VERSION 5.8 ;
BUSBITCHARS "[]" ;
DIVIDERCHAR "/" ;
UNITS
    DATABASE MICRONS 1000 ;
END UNITS

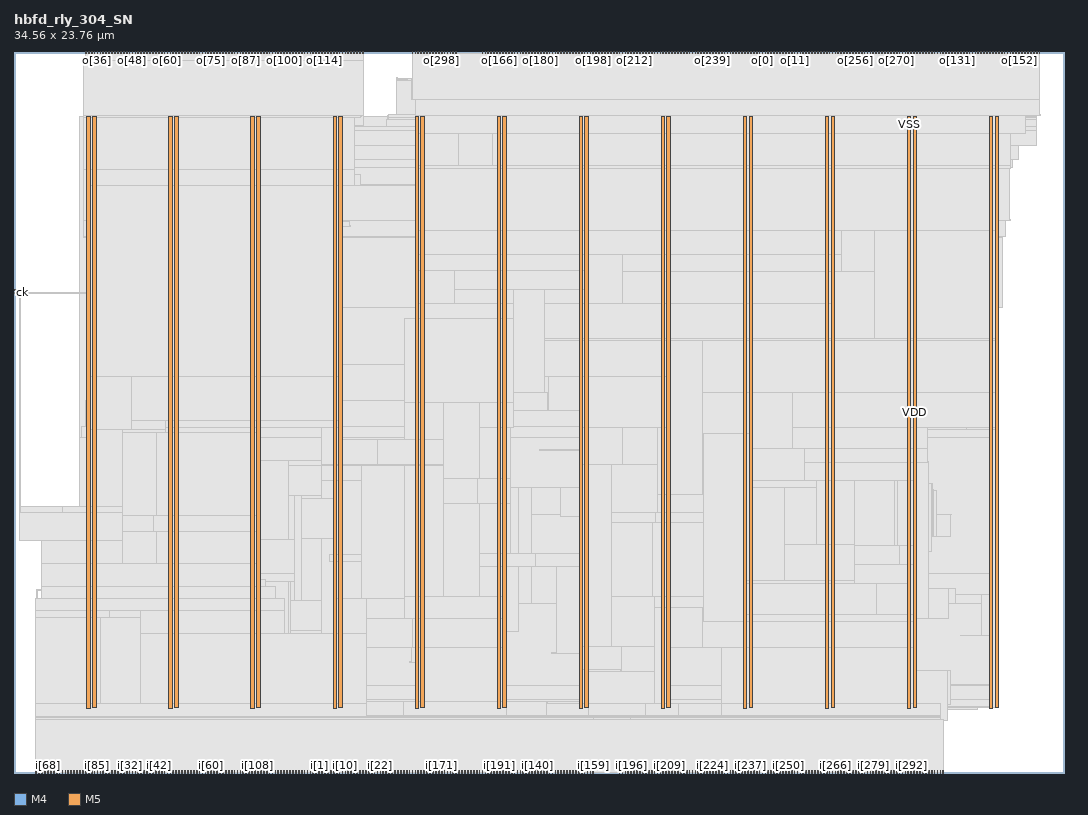
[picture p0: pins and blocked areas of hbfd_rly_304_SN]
MACRO hbfd_rly_304_SN
  FOREIGN hbfd_rly_304_SN 0 0 ;
  CLASS BLOCK ;
  SIZE 34.56 BY 23.76 ;
  PIN ck
    DIRECTION INPUT ;
    USE SIGNAL ;
    PORT
      LAYER M4 ;
        RECT  0 15.792 0.084 15.816 ;
    END
  END ck
  PIN i[0]
    DIRECTION INPUT ;
    USE SIGNAL ;
    PORT
      LAYER M5 ;
        RECT  9.936 0 9.96 0.084 ;
    END
  END i[0]
  PIN i[100]
    DIRECTION INPUT ;
    USE SIGNAL ;
    PORT
      LAYER M5 ;
        RECT  7.248 0 7.272 0.084 ;
    END
  END i[100]
  PIN i[101]
    DIRECTION INPUT ;
    USE SIGNAL ;
    PORT
      LAYER M5 ;
        RECT  7.344 0 7.368 0.084 ;
    END
  END i[101]
  PIN i[102]
    DIRECTION INPUT ;
    USE SIGNAL ;
    PORT
      LAYER M5 ;
        RECT  7.44 0 7.464 0.084 ;
    END
  END i[102]
  PIN i[103]
    DIRECTION INPUT ;
    USE SIGNAL ;
    PORT
      LAYER M5 ;
        RECT  7.536 0 7.56 0.084 ;
    END
  END i[103]
  PIN i[104]
    DIRECTION INPUT ;
    USE SIGNAL ;
    PORT
      LAYER M5 ;
        RECT  7.632 0 7.656 0.084 ;
    END
  END i[104]
  PIN i[105]
    DIRECTION INPUT ;
    USE SIGNAL ;
    PORT
      LAYER M5 ;
        RECT  7.728 0 7.752 0.084 ;
    END
  END i[105]
  PIN i[106]
    DIRECTION INPUT ;
    USE SIGNAL ;
    PORT
      LAYER M5 ;
        RECT  7.824 0 7.848 0.084 ;
    END
  END i[106]
  PIN i[107]
    DIRECTION INPUT ;
    USE SIGNAL ;
    PORT
      LAYER M5 ;
        RECT  7.92 0 7.944 0.084 ;
    END
  END i[107]
  PIN i[108]
    DIRECTION INPUT ;
    USE SIGNAL ;
    PORT
      LAYER M5 ;
        RECT  8.016 0 8.04 0.084 ;
    END
  END i[108]
  PIN i[109]
    DIRECTION INPUT ;
    USE SIGNAL ;
    PORT
      LAYER M5 ;
        RECT  8.112 0 8.136 0.084 ;
    END
  END i[109]
  PIN i[10]
    DIRECTION INPUT ;
    USE SIGNAL ;
    PORT
      LAYER M5 ;
        RECT  10.896 0 10.92 0.084 ;
    END
  END i[10]
  PIN i[110]
    DIRECTION INPUT ;
    USE SIGNAL ;
    PORT
      LAYER M5 ;
        RECT  8.208 0 8.232 0.084 ;
    END
  END i[110]
  PIN i[111]
    DIRECTION INPUT ;
    USE SIGNAL ;
    PORT
      LAYER M5 ;
        RECT  8.304 0 8.328 0.084 ;
    END
  END i[111]
  PIN i[112]
    DIRECTION INPUT ;
    USE SIGNAL ;
    PORT
      LAYER M5 ;
        RECT  8.4 0 8.424 0.084 ;
    END
  END i[112]
  PIN i[113]
    DIRECTION INPUT ;
    USE SIGNAL ;
    PORT
      LAYER M5 ;
        RECT  8.496 0 8.52 0.084 ;
    END
  END i[113]
  PIN i[114]
    DIRECTION INPUT ;
    USE SIGNAL ;
    PORT
      LAYER M5 ;
        RECT  8.592 0 8.616 0.084 ;
    END
  END i[114]
  PIN i[115]
    DIRECTION INPUT ;
    USE SIGNAL ;
    PORT
      LAYER M5 ;
        RECT  8.688 0 8.712 0.084 ;
    END
  END i[115]
  PIN i[116]
    DIRECTION INPUT ;
    USE SIGNAL ;
    PORT
      LAYER M5 ;
        RECT  8.784 0 8.808 0.084 ;
    END
  END i[116]
  PIN i[117]
    DIRECTION INPUT ;
    USE SIGNAL ;
    PORT
      LAYER M5 ;
        RECT  8.88 0 8.904 0.084 ;
    END
  END i[117]
  PIN i[118]
    DIRECTION INPUT ;
    USE SIGNAL ;
    PORT
      LAYER M5 ;
        RECT  8.976 0 9 0.084 ;
    END
  END i[118]
  PIN i[119]
    DIRECTION INPUT ;
    USE SIGNAL ;
    PORT
      LAYER M5 ;
        RECT  9.072 0 9.096 0.084 ;
    END
  END i[119]
  PIN i[11]
    DIRECTION INPUT ;
    USE SIGNAL ;
    PORT
      LAYER M5 ;
        RECT  10.992 0 11.016 0.084 ;
    END
  END i[11]
  PIN i[120]
    DIRECTION INPUT ;
    USE SIGNAL ;
    PORT
      LAYER M5 ;
        RECT  9.168 0 9.192 0.084 ;
    END
  END i[120]
  PIN i[121]
    DIRECTION INPUT ;
    USE SIGNAL ;
    PORT
      LAYER M5 ;
        RECT  9.264 0 9.288 0.084 ;
    END
  END i[121]
  PIN i[122]
    DIRECTION INPUT ;
    USE SIGNAL ;
    PORT
      LAYER M5 ;
        RECT  9.36 0 9.384 0.084 ;
    END
  END i[122]
  PIN i[123]
    DIRECTION INPUT ;
    USE SIGNAL ;
    PORT
      LAYER M5 ;
        RECT  9.456 0 9.48 0.084 ;
    END
  END i[123]
  PIN i[124]
    DIRECTION INPUT ;
    USE SIGNAL ;
    PORT
      LAYER M5 ;
        RECT  9.552 0 9.576 0.084 ;
    END
  END i[124]
  PIN i[125]
    DIRECTION INPUT ;
    USE SIGNAL ;
    PORT
      LAYER M5 ;
        RECT  9.648 0 9.672 0.084 ;
    END
  END i[125]
  PIN i[126]
    DIRECTION INPUT ;
    USE SIGNAL ;
    PORT
      LAYER M5 ;
        RECT  9.744 0 9.768 0.084 ;
    END
  END i[126]
  PIN i[127]
    DIRECTION INPUT ;
    USE SIGNAL ;
    PORT
      LAYER M5 ;
        RECT  9.84 0 9.864 0.084 ;
    END
  END i[127]
  PIN i[128]
    DIRECTION INPUT ;
    USE SIGNAL ;
    PORT
      LAYER M5 ;
        RECT  16.08 0 16.104 0.084 ;
    END
  END i[128]
  PIN i[129]
    DIRECTION INPUT ;
    USE SIGNAL ;
    PORT
      LAYER M5 ;
        RECT  16.176 0 16.2 0.084 ;
    END
  END i[129]
  PIN i[12]
    DIRECTION INPUT ;
    USE SIGNAL ;
    PORT
      LAYER M5 ;
        RECT  11.088 0 11.112 0.084 ;
    END
  END i[12]
  PIN i[130]
    DIRECTION INPUT ;
    USE SIGNAL ;
    PORT
      LAYER M5 ;
        RECT  16.272 0 16.296 0.084 ;
    END
  END i[130]
  PIN i[131]
    DIRECTION INPUT ;
    USE SIGNAL ;
    PORT
      LAYER M5 ;
        RECT  16.368 0 16.392 0.084 ;
    END
  END i[131]
  PIN i[132]
    DIRECTION INPUT ;
    USE SIGNAL ;
    PORT
      LAYER M5 ;
        RECT  16.464 0 16.488 0.084 ;
    END
  END i[132]
  PIN i[133]
    DIRECTION INPUT ;
    USE SIGNAL ;
    PORT
      LAYER M5 ;
        RECT  16.56 0 16.584 0.084 ;
    END
  END i[133]
  PIN i[134]
    DIRECTION INPUT ;
    USE SIGNAL ;
    PORT
      LAYER M5 ;
        RECT  16.656 0 16.68 0.084 ;
    END
  END i[134]
  PIN i[135]
    DIRECTION INPUT ;
    USE SIGNAL ;
    PORT
      LAYER M5 ;
        RECT  16.752 0 16.776 0.084 ;
    END
  END i[135]
  PIN i[136]
    DIRECTION INPUT ;
    USE SIGNAL ;
    PORT
      LAYER M5 ;
        RECT  16.848 0 16.872 0.084 ;
    END
  END i[136]
  PIN i[137]
    DIRECTION INPUT ;
    USE SIGNAL ;
    PORT
      LAYER M5 ;
        RECT  16.944 0 16.968 0.084 ;
    END
  END i[137]
  PIN i[138]
    DIRECTION INPUT ;
    USE SIGNAL ;
    PORT
      LAYER M5 ;
        RECT  17.04 0 17.064 0.084 ;
    END
  END i[138]
  PIN i[139]
    DIRECTION INPUT ;
    USE SIGNAL ;
    PORT
      LAYER M5 ;
        RECT  17.136 0 17.16 0.084 ;
    END
  END i[139]
  PIN i[13]
    DIRECTION INPUT ;
    USE SIGNAL ;
    PORT
      LAYER M5 ;
        RECT  11.184 0 11.208 0.084 ;
    END
  END i[13]
  PIN i[140]
    DIRECTION INPUT ;
    USE SIGNAL ;
    PORT
      LAYER M5 ;
        RECT  17.232 0 17.256 0.084 ;
    END
  END i[140]
  PIN i[141]
    DIRECTION INPUT ;
    USE SIGNAL ;
    PORT
      LAYER M5 ;
        RECT  17.328 0 17.352 0.084 ;
    END
  END i[141]
  PIN i[142]
    DIRECTION INPUT ;
    USE SIGNAL ;
    PORT
      LAYER M5 ;
        RECT  17.424 0 17.448 0.084 ;
    END
  END i[142]
  PIN i[143]
    DIRECTION INPUT ;
    USE SIGNAL ;
    PORT
      LAYER M5 ;
        RECT  17.52 0 17.544 0.084 ;
    END
  END i[143]
  PIN i[144]
    DIRECTION INPUT ;
    USE SIGNAL ;
    PORT
      LAYER M5 ;
        RECT  17.616 0 17.64 0.084 ;
    END
  END i[144]
  PIN i[145]
    DIRECTION INPUT ;
    USE SIGNAL ;
    PORT
      LAYER M5 ;
        RECT  17.712 0 17.736 0.084 ;
    END
  END i[145]
  PIN i[146]
    DIRECTION INPUT ;
    USE SIGNAL ;
    PORT
      LAYER M5 ;
        RECT  17.808 0 17.832 0.084 ;
    END
  END i[146]
  PIN i[147]
    DIRECTION INPUT ;
    USE SIGNAL ;
    PORT
      LAYER M5 ;
        RECT  17.904 0 17.928 0.084 ;
    END
  END i[147]
  PIN i[148]
    DIRECTION INPUT ;
    USE SIGNAL ;
    PORT
      LAYER M5 ;
        RECT  18 0 18.024 0.084 ;
    END
  END i[148]
  PIN i[149]
    DIRECTION INPUT ;
    USE SIGNAL ;
    PORT
      LAYER M5 ;
        RECT  18.096 0 18.12 0.084 ;
    END
  END i[149]
  PIN i[14]
    DIRECTION INPUT ;
    USE SIGNAL ;
    PORT
      LAYER M5 ;
        RECT  11.28 0 11.304 0.084 ;
    END
  END i[14]
  PIN i[150]
    DIRECTION INPUT ;
    USE SIGNAL ;
    PORT
      LAYER M5 ;
        RECT  18.192 0 18.216 0.084 ;
    END
  END i[150]
  PIN i[151]
    DIRECTION INPUT ;
    USE SIGNAL ;
    PORT
      LAYER M5 ;
        RECT  18.288 0 18.312 0.084 ;
    END
  END i[151]
  PIN i[152]
    DIRECTION INPUT ;
    USE SIGNAL ;
    PORT
      LAYER M5 ;
        RECT  18.384 0 18.408 0.084 ;
    END
  END i[152]
  PIN i[153]
    DIRECTION INPUT ;
    USE SIGNAL ;
    PORT
      LAYER M5 ;
        RECT  18.48 0 18.504 0.084 ;
    END
  END i[153]
  PIN i[154]
    DIRECTION INPUT ;
    USE SIGNAL ;
    PORT
      LAYER M5 ;
        RECT  18.576 0 18.6 0.084 ;
    END
  END i[154]
  PIN i[155]
    DIRECTION INPUT ;
    USE SIGNAL ;
    PORT
      LAYER M5 ;
        RECT  18.672 0 18.696 0.084 ;
    END
  END i[155]
  PIN i[156]
    DIRECTION INPUT ;
    USE SIGNAL ;
    PORT
      LAYER M5 ;
        RECT  18.768 0 18.792 0.084 ;
    END
  END i[156]
  PIN i[157]
    DIRECTION INPUT ;
    USE SIGNAL ;
    PORT
      LAYER M5 ;
        RECT  18.864 0 18.888 0.084 ;
    END
  END i[157]
  PIN i[158]
    DIRECTION INPUT ;
    USE SIGNAL ;
    PORT
      LAYER M5 ;
        RECT  18.96 0 18.984 0.084 ;
    END
  END i[158]
  PIN i[159]
    DIRECTION INPUT ;
    USE SIGNAL ;
    PORT
      LAYER M5 ;
        RECT  19.056 0 19.08 0.084 ;
    END
  END i[159]
  PIN i[15]
    DIRECTION INPUT ;
    USE SIGNAL ;
    PORT
      LAYER M5 ;
        RECT  11.376 0 11.4 0.084 ;
    END
  END i[15]
  PIN i[160]
    DIRECTION INPUT ;
    USE SIGNAL ;
    PORT
      LAYER M5 ;
        RECT  13.008 0 13.032 0.084 ;
    END
  END i[160]
  PIN i[161]
    DIRECTION INPUT ;
    USE SIGNAL ;
    PORT
      LAYER M5 ;
        RECT  13.104 0 13.128 0.084 ;
    END
  END i[161]
  PIN i[162]
    DIRECTION INPUT ;
    USE SIGNAL ;
    PORT
      LAYER M5 ;
        RECT  13.2 0 13.224 0.084 ;
    END
  END i[162]
  PIN i[163]
    DIRECTION INPUT ;
    USE SIGNAL ;
    PORT
      LAYER M5 ;
        RECT  13.296 0 13.32 0.084 ;
    END
  END i[163]
  PIN i[164]
    DIRECTION INPUT ;
    USE SIGNAL ;
    PORT
      LAYER M5 ;
        RECT  13.392 0 13.416 0.084 ;
    END
  END i[164]
  PIN i[165]
    DIRECTION INPUT ;
    USE SIGNAL ;
    PORT
      LAYER M5 ;
        RECT  13.488 0 13.512 0.084 ;
    END
  END i[165]
  PIN i[166]
    DIRECTION INPUT ;
    USE SIGNAL ;
    PORT
      LAYER M5 ;
        RECT  13.584 0 13.608 0.084 ;
    END
  END i[166]
  PIN i[167]
    DIRECTION INPUT ;
    USE SIGNAL ;
    PORT
      LAYER M5 ;
        RECT  13.68 0 13.704 0.084 ;
    END
  END i[167]
  PIN i[168]
    DIRECTION INPUT ;
    USE SIGNAL ;
    PORT
      LAYER M5 ;
        RECT  13.776 0 13.8 0.084 ;
    END
  END i[168]
  PIN i[169]
    DIRECTION INPUT ;
    USE SIGNAL ;
    PORT
      LAYER M5 ;
        RECT  13.872 0 13.896 0.084 ;
    END
  END i[169]
  PIN i[16]
    DIRECTION INPUT ;
    USE SIGNAL ;
    PORT
      LAYER M5 ;
        RECT  11.472 0 11.496 0.084 ;
    END
  END i[16]
  PIN i[170]
    DIRECTION INPUT ;
    USE SIGNAL ;
    PORT
      LAYER M5 ;
        RECT  13.968 0 13.992 0.084 ;
    END
  END i[170]
  PIN i[171]
    DIRECTION INPUT ;
    USE SIGNAL ;
    PORT
      LAYER M5 ;
        RECT  14.064 0 14.088 0.084 ;
    END
  END i[171]
  PIN i[172]
    DIRECTION INPUT ;
    USE SIGNAL ;
    PORT
      LAYER M5 ;
        RECT  14.16 0 14.184 0.084 ;
    END
  END i[172]
  PIN i[173]
    DIRECTION INPUT ;
    USE SIGNAL ;
    PORT
      LAYER M5 ;
        RECT  14.256 0 14.28 0.084 ;
    END
  END i[173]
  PIN i[174]
    DIRECTION INPUT ;
    USE SIGNAL ;
    PORT
      LAYER M5 ;
        RECT  14.352 0 14.376 0.084 ;
    END
  END i[174]
  PIN i[175]
    DIRECTION INPUT ;
    USE SIGNAL ;
    PORT
      LAYER M5 ;
        RECT  14.448 0 14.472 0.084 ;
    END
  END i[175]
  PIN i[176]
    DIRECTION INPUT ;
    USE SIGNAL ;
    PORT
      LAYER M5 ;
        RECT  14.544 0 14.568 0.084 ;
    END
  END i[176]
  PIN i[177]
    DIRECTION INPUT ;
    USE SIGNAL ;
    PORT
      LAYER M5 ;
        RECT  14.64 0 14.664 0.084 ;
    END
  END i[177]
  PIN i[178]
    DIRECTION INPUT ;
    USE SIGNAL ;
    PORT
      LAYER M5 ;
        RECT  14.736 0 14.76 0.084 ;
    END
  END i[178]
  PIN i[179]
    DIRECTION INPUT ;
    USE SIGNAL ;
    PORT
      LAYER M5 ;
        RECT  14.832 0 14.856 0.084 ;
    END
  END i[179]
  PIN i[17]
    DIRECTION INPUT ;
    USE SIGNAL ;
    PORT
      LAYER M5 ;
        RECT  11.568 0 11.592 0.084 ;
    END
  END i[17]
  PIN i[180]
    DIRECTION INPUT ;
    USE SIGNAL ;
    PORT
      LAYER M5 ;
        RECT  14.928 0 14.952 0.084 ;
    END
  END i[180]
  PIN i[181]
    DIRECTION INPUT ;
    USE SIGNAL ;
    PORT
      LAYER M5 ;
        RECT  15.024 0 15.048 0.084 ;
    END
  END i[181]
  PIN i[182]
    DIRECTION INPUT ;
    USE SIGNAL ;
    PORT
      LAYER M5 ;
        RECT  15.12 0 15.144 0.084 ;
    END
  END i[182]
  PIN i[183]
    DIRECTION INPUT ;
    USE SIGNAL ;
    PORT
      LAYER M5 ;
        RECT  15.216 0 15.24 0.084 ;
    END
  END i[183]
  PIN i[184]
    DIRECTION INPUT ;
    USE SIGNAL ;
    PORT
      LAYER M5 ;
        RECT  15.312 0 15.336 0.084 ;
    END
  END i[184]
  PIN i[185]
    DIRECTION INPUT ;
    USE SIGNAL ;
    PORT
      LAYER M5 ;
        RECT  15.408 0 15.432 0.084 ;
    END
  END i[185]
  PIN i[186]
    DIRECTION INPUT ;
    USE SIGNAL ;
    PORT
      LAYER M5 ;
        RECT  15.504 0 15.528 0.084 ;
    END
  END i[186]
  PIN i[187]
    DIRECTION INPUT ;
    USE SIGNAL ;
    PORT
      LAYER M5 ;
        RECT  15.6 0 15.624 0.084 ;
    END
  END i[187]
  PIN i[188]
    DIRECTION INPUT ;
    USE SIGNAL ;
    PORT
      LAYER M5 ;
        RECT  15.696 0 15.72 0.084 ;
    END
  END i[188]
  PIN i[189]
    DIRECTION INPUT ;
    USE SIGNAL ;
    PORT
      LAYER M5 ;
        RECT  15.792 0 15.816 0.084 ;
    END
  END i[189]
  PIN i[18]
    DIRECTION INPUT ;
    USE SIGNAL ;
    PORT
      LAYER M5 ;
        RECT  11.664 0 11.688 0.084 ;
    END
  END i[18]
  PIN i[190]
    DIRECTION INPUT ;
    USE SIGNAL ;
    PORT
      LAYER M5 ;
        RECT  15.888 0 15.912 0.084 ;
    END
  END i[190]
  PIN i[191]
    DIRECTION INPUT ;
    USE SIGNAL ;
    PORT
      LAYER M5 ;
        RECT  15.984 0 16.008 0.084 ;
    END
  END i[191]
  PIN i[192]
    DIRECTION INPUT ;
    USE SIGNAL ;
    PORT
      LAYER M5 ;
        RECT  19.92 0 19.944 0.084 ;
    END
  END i[192]
  PIN i[193]
    DIRECTION INPUT ;
    USE SIGNAL ;
    PORT
      LAYER M5 ;
        RECT  20.016 0 20.04 0.084 ;
    END
  END i[193]
  PIN i[194]
    DIRECTION INPUT ;
    USE SIGNAL ;
    PORT
      LAYER M5 ;
        RECT  20.112 0 20.136 0.084 ;
    END
  END i[194]
  PIN i[195]
    DIRECTION INPUT ;
    USE SIGNAL ;
    PORT
      LAYER M5 ;
        RECT  20.208 0 20.232 0.084 ;
    END
  END i[195]
  PIN i[196]
    DIRECTION INPUT ;
    USE SIGNAL ;
    PORT
      LAYER M5 ;
        RECT  20.304 0 20.328 0.084 ;
    END
  END i[196]
  PIN i[197]
    DIRECTION INPUT ;
    USE SIGNAL ;
    PORT
      LAYER M5 ;
        RECT  20.4 0 20.424 0.084 ;
    END
  END i[197]
  PIN i[198]
    DIRECTION INPUT ;
    USE SIGNAL ;
    PORT
      LAYER M5 ;
        RECT  20.496 0 20.52 0.084 ;
    END
  END i[198]
  PIN i[199]
    DIRECTION INPUT ;
    USE SIGNAL ;
    PORT
      LAYER M5 ;
        RECT  20.592 0 20.616 0.084 ;
    END
  END i[199]
  PIN i[19]
    DIRECTION INPUT ;
    USE SIGNAL ;
    PORT
      LAYER M5 ;
        RECT  11.76 0 11.784 0.084 ;
    END
  END i[19]
  PIN i[1]
    DIRECTION INPUT ;
    USE SIGNAL ;
    PORT
      LAYER M5 ;
        RECT  10.032 0 10.056 0.084 ;
    END
  END i[1]
  PIN i[200]
    DIRECTION INPUT ;
    USE SIGNAL ;
    PORT
      LAYER M5 ;
        RECT  20.688 0 20.712 0.084 ;
    END
  END i[200]
  PIN i[201]
    DIRECTION INPUT ;
    USE SIGNAL ;
    PORT
      LAYER M5 ;
        RECT  20.784 0 20.808 0.084 ;
    END
  END i[201]
  PIN i[202]
    DIRECTION INPUT ;
    USE SIGNAL ;
    PORT
      LAYER M5 ;
        RECT  20.88 0 20.904 0.084 ;
    END
  END i[202]
  PIN i[203]
    DIRECTION INPUT ;
    USE SIGNAL ;
    PORT
      LAYER M5 ;
        RECT  20.976 0 21 0.084 ;
    END
  END i[203]
  PIN i[204]
    DIRECTION INPUT ;
    USE SIGNAL ;
    PORT
      LAYER M5 ;
        RECT  21.072 0 21.096 0.084 ;
    END
  END i[204]
  PIN i[205]
    DIRECTION INPUT ;
    USE SIGNAL ;
    PORT
      LAYER M5 ;
        RECT  21.168 0 21.192 0.084 ;
    END
  END i[205]
  PIN i[206]
    DIRECTION INPUT ;
    USE SIGNAL ;
    PORT
      LAYER M5 ;
        RECT  21.264 0 21.288 0.084 ;
    END
  END i[206]
  PIN i[207]
    DIRECTION INPUT ;
    USE SIGNAL ;
    PORT
      LAYER M5 ;
        RECT  21.36 0 21.384 0.084 ;
    END
  END i[207]
  PIN i[208]
    DIRECTION INPUT ;
    USE SIGNAL ;
    PORT
      LAYER M5 ;
        RECT  21.456 0 21.48 0.084 ;
    END
  END i[208]
  PIN i[209]
    DIRECTION INPUT ;
    USE SIGNAL ;
    PORT
      LAYER M5 ;
        RECT  21.552 0 21.576 0.084 ;
    END
  END i[209]
  PIN i[20]
    DIRECTION INPUT ;
    USE SIGNAL ;
    PORT
      LAYER M5 ;
        RECT  11.856 0 11.88 0.084 ;
    END
  END i[20]
  PIN i[210]
    DIRECTION INPUT ;
    USE SIGNAL ;
    PORT
      LAYER M5 ;
        RECT  21.648 0 21.672 0.084 ;
    END
  END i[210]
  PIN i[211]
    DIRECTION INPUT ;
    USE SIGNAL ;
    PORT
      LAYER M5 ;
        RECT  21.744 0 21.768 0.084 ;
    END
  END i[211]
  PIN i[212]
    DIRECTION INPUT ;
    USE SIGNAL ;
    PORT
      LAYER M5 ;
        RECT  21.84 0 21.864 0.084 ;
    END
  END i[212]
  PIN i[213]
    DIRECTION INPUT ;
    USE SIGNAL ;
    PORT
      LAYER M5 ;
        RECT  21.936 0 21.96 0.084 ;
    END
  END i[213]
  PIN i[214]
    DIRECTION INPUT ;
    USE SIGNAL ;
    PORT
      LAYER M5 ;
        RECT  22.032 0 22.056 0.084 ;
    END
  END i[214]
  PIN i[215]
    DIRECTION INPUT ;
    USE SIGNAL ;
    PORT
      LAYER M5 ;
        RECT  22.128 0 22.152 0.084 ;
    END
  END i[215]
  PIN i[216]
    DIRECTION INPUT ;
    USE SIGNAL ;
    PORT
      LAYER M5 ;
        RECT  22.224 0 22.248 0.084 ;
    END
  END i[216]
  PIN i[217]
    DIRECTION INPUT ;
    USE SIGNAL ;
    PORT
      LAYER M5 ;
        RECT  22.32 0 22.344 0.084 ;
    END
  END i[217]
  PIN i[218]
    DIRECTION INPUT ;
    USE SIGNAL ;
    PORT
      LAYER M5 ;
        RECT  22.416 0 22.44 0.084 ;
    END
  END i[218]
  PIN i[219]
    DIRECTION INPUT ;
    USE SIGNAL ;
    PORT
      LAYER M5 ;
        RECT  22.512 0 22.536 0.084 ;
    END
  END i[219]
  PIN i[21]
    DIRECTION INPUT ;
    USE SIGNAL ;
    PORT
      LAYER M5 ;
        RECT  11.952 0 11.976 0.084 ;
    END
  END i[21]
  PIN i[220]
    DIRECTION INPUT ;
    USE SIGNAL ;
    PORT
      LAYER M5 ;
        RECT  22.608 0 22.632 0.084 ;
    END
  END i[220]
  PIN i[221]
    DIRECTION INPUT ;
    USE SIGNAL ;
    PORT
      LAYER M5 ;
        RECT  22.704 0 22.728 0.084 ;
    END
  END i[221]
  PIN i[222]
    DIRECTION INPUT ;
    USE SIGNAL ;
    PORT
      LAYER M5 ;
        RECT  22.8 0 22.824 0.084 ;
    END
  END i[222]
  PIN i[223]
    DIRECTION INPUT ;
    USE SIGNAL ;
    PORT
      LAYER M5 ;
        RECT  22.896 0 22.92 0.084 ;
    END
  END i[223]
  PIN i[224]
    DIRECTION INPUT ;
    USE SIGNAL ;
    PORT
      LAYER M5 ;
        RECT  22.992 0 23.016 0.084 ;
    END
  END i[224]
  PIN i[225]
    DIRECTION INPUT ;
    USE SIGNAL ;
    PORT
      LAYER M5 ;
        RECT  23.088 0 23.112 0.084 ;
    END
  END i[225]
  PIN i[226]
    DIRECTION INPUT ;
    USE SIGNAL ;
    PORT
      LAYER M5 ;
        RECT  23.184 0 23.208 0.084 ;
    END
  END i[226]
  PIN i[227]
    DIRECTION INPUT ;
    USE SIGNAL ;
    PORT
      LAYER M5 ;
        RECT  23.28 0 23.304 0.084 ;
    END
  END i[227]
  PIN i[228]
    DIRECTION INPUT ;
    USE SIGNAL ;
    PORT
      LAYER M5 ;
        RECT  23.376 0 23.4 0.084 ;
    END
  END i[228]
  PIN i[229]
    DIRECTION INPUT ;
    USE SIGNAL ;
    PORT
      LAYER M5 ;
        RECT  23.472 0 23.496 0.084 ;
    END
  END i[229]
  PIN i[22]
    DIRECTION INPUT ;
    USE SIGNAL ;
    PORT
      LAYER M5 ;
        RECT  12.048 0 12.072 0.084 ;
    END
  END i[22]
  PIN i[230]
    DIRECTION INPUT ;
    USE SIGNAL ;
    PORT
      LAYER M5 ;
        RECT  23.568 0 23.592 0.084 ;
    END
  END i[230]
  PIN i[231]
    DIRECTION INPUT ;
    USE SIGNAL ;
    PORT
      LAYER M5 ;
        RECT  23.664 0 23.688 0.084 ;
    END
  END i[231]
  PIN i[232]
    DIRECTION INPUT ;
    USE SIGNAL ;
    PORT
      LAYER M5 ;
        RECT  23.76 0 23.784 0.084 ;
    END
  END i[232]
  PIN i[233]
    DIRECTION INPUT ;
    USE SIGNAL ;
    PORT
      LAYER M5 ;
        RECT  23.856 0 23.88 0.084 ;
    END
  END i[233]
  PIN i[234]
    DIRECTION INPUT ;
    USE SIGNAL ;
    PORT
      LAYER M5 ;
        RECT  23.952 0 23.976 0.084 ;
    END
  END i[234]
  PIN i[235]
    DIRECTION INPUT ;
    USE SIGNAL ;
    PORT
      LAYER M5 ;
        RECT  24.048 0 24.072 0.084 ;
    END
  END i[235]
  PIN i[236]
    DIRECTION INPUT ;
    USE SIGNAL ;
    PORT
      LAYER M5 ;
        RECT  24.144 0 24.168 0.084 ;
    END
  END i[236]
  PIN i[237]
    DIRECTION INPUT ;
    USE SIGNAL ;
    PORT
      LAYER M5 ;
        RECT  24.24 0 24.264 0.084 ;
    END
  END i[237]
  PIN i[238]
    DIRECTION INPUT ;
    USE SIGNAL ;
    PORT
      LAYER M5 ;
        RECT  24.336 0 24.36 0.084 ;
    END
  END i[238]
  PIN i[239]
    DIRECTION INPUT ;
    USE SIGNAL ;
    PORT
      LAYER M5 ;
        RECT  24.432 0 24.456 0.084 ;
    END
  END i[239]
  PIN i[23]
    DIRECTION INPUT ;
    USE SIGNAL ;
    PORT
      LAYER M5 ;
        RECT  12.144 0 12.168 0.084 ;
    END
  END i[23]
  PIN i[240]
    DIRECTION INPUT ;
    USE SIGNAL ;
    PORT
      LAYER M5 ;
        RECT  24.528 0 24.552 0.084 ;
    END
  END i[240]
  PIN i[241]
    DIRECTION INPUT ;
    USE SIGNAL ;
    PORT
      LAYER M5 ;
        RECT  24.624 0 24.648 0.084 ;
    END
  END i[241]
  PIN i[242]
    DIRECTION INPUT ;
    USE SIGNAL ;
    PORT
      LAYER M5 ;
        RECT  24.72 0 24.744 0.084 ;
    END
  END i[242]
  PIN i[243]
    DIRECTION INPUT ;
    USE SIGNAL ;
    PORT
      LAYER M5 ;
        RECT  24.816 0 24.84 0.084 ;
    END
  END i[243]
  PIN i[244]
    DIRECTION INPUT ;
    USE SIGNAL ;
    PORT
      LAYER M5 ;
        RECT  24.912 0 24.936 0.084 ;
    END
  END i[244]
  PIN i[245]
    DIRECTION INPUT ;
    USE SIGNAL ;
    PORT
      LAYER M5 ;
        RECT  25.008 0 25.032 0.084 ;
    END
  END i[245]
  PIN i[246]
    DIRECTION INPUT ;
    USE SIGNAL ;
    PORT
      LAYER M5 ;
        RECT  25.104 0 25.128 0.084 ;
    END
  END i[246]
  PIN i[247]
    DIRECTION INPUT ;
    USE SIGNAL ;
    PORT
      LAYER M5 ;
        RECT  25.2 0 25.224 0.084 ;
    END
  END i[247]
  PIN i[248]
    DIRECTION INPUT ;
    USE SIGNAL ;
    PORT
      LAYER M5 ;
        RECT  25.296 0 25.32 0.084 ;
    END
  END i[248]
  PIN i[249]
    DIRECTION INPUT ;
    USE SIGNAL ;
    PORT
      LAYER M5 ;
        RECT  25.392 0 25.416 0.084 ;
    END
  END i[249]
  PIN i[24]
    DIRECTION INPUT ;
    USE SIGNAL ;
    PORT
      LAYER M5 ;
        RECT  12.24 0 12.264 0.084 ;
    END
  END i[24]
  PIN i[250]
    DIRECTION INPUT ;
    USE SIGNAL ;
    PORT
      LAYER M5 ;
        RECT  25.488 0 25.512 0.084 ;
    END
  END i[250]
  PIN i[251]
    DIRECTION INPUT ;
    USE SIGNAL ;
    PORT
      LAYER M5 ;
        RECT  25.584 0 25.608 0.084 ;
    END
  END i[251]
  PIN i[252]
    DIRECTION INPUT ;
    USE SIGNAL ;
    PORT
      LAYER M5 ;
        RECT  25.68 0 25.704 0.084 ;
    END
  END i[252]
  PIN i[253]
    DIRECTION INPUT ;
    USE SIGNAL ;
    PORT
      LAYER M5 ;
        RECT  25.776 0 25.8 0.084 ;
    END
  END i[253]
  PIN i[254]
    DIRECTION INPUT ;
    USE SIGNAL ;
    PORT
      LAYER M5 ;
        RECT  25.872 0 25.896 0.084 ;
    END
  END i[254]
  PIN i[255]
    DIRECTION INPUT ;
    USE SIGNAL ;
    PORT
      LAYER M5 ;
        RECT  25.968 0 25.992 0.084 ;
    END
  END i[255]
  PIN i[256]
    DIRECTION INPUT ;
    USE SIGNAL ;
    PORT
      LAYER M5 ;
        RECT  26.064 0 26.088 0.084 ;
    END
  END i[256]
  PIN i[257]
    DIRECTION INPUT ;
    USE SIGNAL ;
    PORT
      LAYER M5 ;
        RECT  26.16 0 26.184 0.084 ;
    END
  END i[257]
  PIN i[258]
    DIRECTION INPUT ;
    USE SIGNAL ;
    PORT
      LAYER M5 ;
        RECT  26.256 0 26.28 0.084 ;
    END
  END i[258]
  PIN i[259]
    DIRECTION INPUT ;
    USE SIGNAL ;
    PORT
      LAYER M5 ;
        RECT  26.352 0 26.376 0.084 ;
    END
  END i[259]
  PIN i[25]
    DIRECTION INPUT ;
    USE SIGNAL ;
    PORT
      LAYER M5 ;
        RECT  12.336 0 12.36 0.084 ;
    END
  END i[25]
  PIN i[260]
    DIRECTION INPUT ;
    USE SIGNAL ;
    PORT
      LAYER M5 ;
        RECT  26.448 0 26.472 0.084 ;
    END
  END i[260]
  PIN i[261]
    DIRECTION INPUT ;
    USE SIGNAL ;
    PORT
      LAYER M5 ;
        RECT  26.544 0 26.568 0.084 ;
    END
  END i[261]
  PIN i[262]
    DIRECTION INPUT ;
    USE SIGNAL ;
    PORT
      LAYER M5 ;
        RECT  26.64 0 26.664 0.084 ;
    END
  END i[262]
  PIN i[263]
    DIRECTION INPUT ;
    USE SIGNAL ;
    PORT
      LAYER M5 ;
        RECT  26.736 0 26.76 0.084 ;
    END
  END i[263]
  PIN i[264]
    DIRECTION INPUT ;
    USE SIGNAL ;
    PORT
      LAYER M5 ;
        RECT  26.832 0 26.856 0.084 ;
    END
  END i[264]
  PIN i[265]
    DIRECTION INPUT ;
    USE SIGNAL ;
    PORT
      LAYER M5 ;
        RECT  26.928 0 26.952 0.084 ;
    END
  END i[265]
  PIN i[266]
    DIRECTION INPUT ;
    USE SIGNAL ;
    PORT
      LAYER M5 ;
        RECT  27.024 0 27.048 0.084 ;
    END
  END i[266]
  PIN i[267]
    DIRECTION INPUT ;
    USE SIGNAL ;
    PORT
      LAYER M5 ;
        RECT  27.12 0 27.144 0.084 ;
    END
  END i[267]
  PIN i[268]
    DIRECTION INPUT ;
    USE SIGNAL ;
    PORT
      LAYER M5 ;
        RECT  27.216 0 27.24 0.084 ;
    END
  END i[268]
  PIN i[269]
    DIRECTION INPUT ;
    USE SIGNAL ;
    PORT
      LAYER M5 ;
        RECT  27.312 0 27.336 0.084 ;
    END
  END i[269]
  PIN i[26]
    DIRECTION INPUT ;
    USE SIGNAL ;
    PORT
      LAYER M5 ;
        RECT  12.432 0 12.456 0.084 ;
    END
  END i[26]
  PIN i[270]
    DIRECTION INPUT ;
    USE SIGNAL ;
    PORT
      LAYER M5 ;
        RECT  27.408 0 27.432 0.084 ;
    END
  END i[270]
  PIN i[271]
    DIRECTION INPUT ;
    USE SIGNAL ;
    PORT
      LAYER M5 ;
        RECT  27.504 0 27.528 0.084 ;
    END
  END i[271]
  PIN i[272]
    DIRECTION INPUT ;
    USE SIGNAL ;
    PORT
      LAYER M5 ;
        RECT  27.6 0 27.624 0.084 ;
    END
  END i[272]
  PIN i[273]
    DIRECTION INPUT ;
    USE SIGNAL ;
    PORT
      LAYER M5 ;
        RECT  27.696 0 27.72 0.084 ;
    END
  END i[273]
  PIN i[274]
    DIRECTION INPUT ;
    USE SIGNAL ;
    PORT
      LAYER M5 ;
        RECT  27.792 0 27.816 0.084 ;
    END
  END i[274]
  PIN i[275]
    DIRECTION INPUT ;
    USE SIGNAL ;
    PORT
      LAYER M5 ;
        RECT  27.888 0 27.912 0.084 ;
    END
  END i[275]
  PIN i[276]
    DIRECTION INPUT ;
    USE SIGNAL ;
    PORT
      LAYER M5 ;
        RECT  27.984 0 28.008 0.084 ;
    END
  END i[276]
  PIN i[277]
    DIRECTION INPUT ;
    USE SIGNAL ;
    PORT
      LAYER M5 ;
        RECT  28.08 0 28.104 0.084 ;
    END
  END i[277]
  PIN i[278]
    DIRECTION INPUT ;
    USE SIGNAL ;
    PORT
      LAYER M5 ;
        RECT  28.176 0 28.2 0.084 ;
    END
  END i[278]
  PIN i[279]
    DIRECTION INPUT ;
    USE SIGNAL ;
    PORT
      LAYER M5 ;
        RECT  28.272 0 28.296 0.084 ;
    END
  END i[279]
  PIN i[27]
    DIRECTION INPUT ;
    USE SIGNAL ;
    PORT
      LAYER M5 ;
        RECT  12.528 0 12.552 0.084 ;
    END
  END i[27]
  PIN i[280]
    DIRECTION INPUT ;
    USE SIGNAL ;
    PORT
      LAYER M5 ;
        RECT  28.368 0 28.392 0.084 ;
    END
  END i[280]
  PIN i[281]
    DIRECTION INPUT ;
    USE SIGNAL ;
    PORT
      LAYER M5 ;
        RECT  28.464 0 28.488 0.084 ;
    END
  END i[281]
  PIN i[282]
    DIRECTION INPUT ;
    USE SIGNAL ;
    PORT
      LAYER M5 ;
        RECT  28.56 0 28.584 0.084 ;
    END
  END i[282]
  PIN i[283]
    DIRECTION INPUT ;
    USE SIGNAL ;
    PORT
      LAYER M5 ;
        RECT  28.656 0 28.68 0.084 ;
    END
  END i[283]
  PIN i[284]
    DIRECTION INPUT ;
    USE SIGNAL ;
    PORT
      LAYER M5 ;
        RECT  28.752 0 28.776 0.084 ;
    END
  END i[284]
  PIN i[285]
    DIRECTION INPUT ;
    USE SIGNAL ;
    PORT
      LAYER M5 ;
        RECT  28.848 0 28.872 0.084 ;
    END
  END i[285]
  PIN i[286]
    DIRECTION INPUT ;
    USE SIGNAL ;
    PORT
      LAYER M5 ;
        RECT  28.944 0 28.968 0.084 ;
    END
  END i[286]
  PIN i[287]
    DIRECTION INPUT ;
    USE SIGNAL ;
    PORT
      LAYER M5 ;
        RECT  29.04 0 29.064 0.084 ;
    END
  END i[287]
  PIN i[288]
    DIRECTION INPUT ;
    USE SIGNAL ;
    PORT
      LAYER M5 ;
        RECT  29.136 0 29.16 0.084 ;
    END
  END i[288]
  PIN i[289]
    DIRECTION INPUT ;
    USE SIGNAL ;
    PORT
      LAYER M5 ;
        RECT  29.232 0 29.256 0.084 ;
    END
  END i[289]
  PIN i[28]
    DIRECTION INPUT ;
    USE SIGNAL ;
    PORT
      LAYER M5 ;
        RECT  12.624 0 12.648 0.084 ;
    END
  END i[28]
  PIN i[290]
    DIRECTION INPUT ;
    USE SIGNAL ;
    PORT
      LAYER M5 ;
        RECT  29.328 0 29.352 0.084 ;
    END
  END i[290]
  PIN i[291]
    DIRECTION INPUT ;
    USE SIGNAL ;
    PORT
      LAYER M5 ;
        RECT  29.424 0 29.448 0.084 ;
    END
  END i[291]
  PIN i[292]
    DIRECTION INPUT ;
    USE SIGNAL ;
    PORT
      LAYER M5 ;
        RECT  29.52 0 29.544 0.084 ;
    END
  END i[292]
  PIN i[293]
    DIRECTION INPUT ;
    USE SIGNAL ;
    PORT
      LAYER M5 ;
        RECT  29.616 0 29.64 0.084 ;
    END
  END i[293]
  PIN i[294]
    DIRECTION INPUT ;
    USE SIGNAL ;
    PORT
      LAYER M5 ;
        RECT  29.712 0 29.736 0.084 ;
    END
  END i[294]
  PIN i[295]
    DIRECTION INPUT ;
    USE SIGNAL ;
    PORT
      LAYER M5 ;
        RECT  29.808 0 29.832 0.084 ;
    END
  END i[295]
  PIN i[296]
    DIRECTION INPUT ;
    USE SIGNAL ;
    PORT
      LAYER M5 ;
        RECT  29.904 0 29.928 0.084 ;
    END
  END i[296]
  PIN i[297]
    DIRECTION INPUT ;
    USE SIGNAL ;
    PORT
      LAYER M5 ;
        RECT  30 0 30.024 0.084 ;
    END
  END i[297]
  PIN i[298]
    DIRECTION INPUT ;
    USE SIGNAL ;
    PORT
      LAYER M5 ;
        RECT  30.096 0 30.12 0.084 ;
    END
  END i[298]
  PIN i[299]
    DIRECTION INPUT ;
    USE SIGNAL ;
    PORT
      LAYER M5 ;
        RECT  30.192 0 30.216 0.084 ;
    END
  END i[299]
  PIN i[29]
    DIRECTION INPUT ;
    USE SIGNAL ;
    PORT
      LAYER M5 ;
        RECT  12.72 0 12.744 0.084 ;
    END
  END i[29]
  PIN i[2]
    DIRECTION INPUT ;
    USE SIGNAL ;
    PORT
      LAYER M5 ;
        RECT  10.128 0 10.152 0.084 ;
    END
  END i[2]
  PIN i[300]
    DIRECTION INPUT ;
    USE SIGNAL ;
    PORT
      LAYER M5 ;
        RECT  30.288 0 30.312 0.084 ;
    END
  END i[300]
  PIN i[301]
    DIRECTION INPUT ;
    USE SIGNAL ;
    PORT
      LAYER M5 ;
        RECT  30.384 0 30.408 0.084 ;
    END
  END i[301]
  PIN i[302]
    DIRECTION INPUT ;
    USE SIGNAL ;
    PORT
      LAYER M5 ;
        RECT  30.48 0 30.504 0.084 ;
    END
  END i[302]
  PIN i[303]
    DIRECTION INPUT ;
    USE SIGNAL ;
    PORT
      LAYER M5 ;
        RECT  30.576 0 30.6 0.084 ;
    END
  END i[303]
  PIN i[30]
    DIRECTION INPUT ;
    USE SIGNAL ;
    PORT
      LAYER M5 ;
        RECT  12.816 0 12.84 0.084 ;
    END
  END i[30]
  PIN i[31]
    DIRECTION INPUT ;
    USE SIGNAL ;
    PORT
      LAYER M5 ;
        RECT  12.912 0 12.936 0.084 ;
    END
  END i[31]
  PIN i[32]
    DIRECTION INPUT ;
    USE SIGNAL ;
    PORT
      LAYER M5 ;
        RECT  3.792 0 3.816 0.084 ;
    END
  END i[32]
  PIN i[33]
    DIRECTION INPUT ;
    USE SIGNAL ;
    PORT
      LAYER M5 ;
        RECT  3.888 0 3.912 0.084 ;
    END
  END i[33]
  PIN i[34]
    DIRECTION INPUT ;
    USE SIGNAL ;
    PORT
      LAYER M5 ;
        RECT  3.984 0 4.008 0.084 ;
    END
  END i[34]
  PIN i[35]
    DIRECTION INPUT ;
    USE SIGNAL ;
    PORT
      LAYER M5 ;
        RECT  4.08 0 4.104 0.084 ;
    END
  END i[35]
  PIN i[36]
    DIRECTION INPUT ;
    USE SIGNAL ;
    PORT
      LAYER M5 ;
        RECT  4.176 0 4.2 0.084 ;
    END
  END i[36]
  PIN i[37]
    DIRECTION INPUT ;
    USE SIGNAL ;
    PORT
      LAYER M5 ;
        RECT  4.272 0 4.296 0.084 ;
    END
  END i[37]
  PIN i[38]
    DIRECTION INPUT ;
    USE SIGNAL ;
    PORT
      LAYER M5 ;
        RECT  4.368 0 4.392 0.084 ;
    END
  END i[38]
  PIN i[39]
    DIRECTION INPUT ;
    USE SIGNAL ;
    PORT
      LAYER M5 ;
        RECT  4.464 0 4.488 0.084 ;
    END
  END i[39]
  PIN i[3]
    DIRECTION INPUT ;
    USE SIGNAL ;
    PORT
      LAYER M5 ;
        RECT  10.224 0 10.248 0.084 ;
    END
  END i[3]
  PIN i[40]
    DIRECTION INPUT ;
    USE SIGNAL ;
    PORT
      LAYER M5 ;
        RECT  4.56 0 4.584 0.084 ;
    END
  END i[40]
  PIN i[41]
    DIRECTION INPUT ;
    USE SIGNAL ;
    PORT
      LAYER M5 ;
        RECT  4.656 0 4.68 0.084 ;
    END
  END i[41]
  PIN i[42]
    DIRECTION INPUT ;
    USE SIGNAL ;
    PORT
      LAYER M5 ;
        RECT  4.752 0 4.776 0.084 ;
    END
  END i[42]
  PIN i[43]
    DIRECTION INPUT ;
    USE SIGNAL ;
    PORT
      LAYER M5 ;
        RECT  4.848 0 4.872 0.084 ;
    END
  END i[43]
  PIN i[44]
    DIRECTION INPUT ;
    USE SIGNAL ;
    PORT
      LAYER M5 ;
        RECT  4.944 0 4.968 0.084 ;
    END
  END i[44]
  PIN i[45]
    DIRECTION INPUT ;
    USE SIGNAL ;
    PORT
      LAYER M5 ;
        RECT  5.04 0 5.064 0.084 ;
    END
  END i[45]
  PIN i[46]
    DIRECTION INPUT ;
    USE SIGNAL ;
    PORT
      LAYER M5 ;
        RECT  5.136 0 5.16 0.084 ;
    END
  END i[46]
  PIN i[47]
    DIRECTION INPUT ;
    USE SIGNAL ;
    PORT
      LAYER M5 ;
        RECT  5.232 0 5.256 0.084 ;
    END
  END i[47]
  PIN i[48]
    DIRECTION INPUT ;
    USE SIGNAL ;
    PORT
      LAYER M5 ;
        RECT  5.328 0 5.352 0.084 ;
    END
  END i[48]
  PIN i[49]
    DIRECTION INPUT ;
    USE SIGNAL ;
    PORT
      LAYER M5 ;
        RECT  5.424 0 5.448 0.084 ;
    END
  END i[49]
  PIN i[4]
    DIRECTION INPUT ;
    USE SIGNAL ;
    PORT
      LAYER M5 ;
        RECT  10.32 0 10.344 0.084 ;
    END
  END i[4]
  PIN i[50]
    DIRECTION INPUT ;
    USE SIGNAL ;
    PORT
      LAYER M5 ;
        RECT  5.52 0 5.544 0.084 ;
    END
  END i[50]
  PIN i[51]
    DIRECTION INPUT ;
    USE SIGNAL ;
    PORT
      LAYER M5 ;
        RECT  5.616 0 5.64 0.084 ;
    END
  END i[51]
  PIN i[52]
    DIRECTION INPUT ;
    USE SIGNAL ;
    PORT
      LAYER M5 ;
        RECT  5.712 0 5.736 0.084 ;
    END
  END i[52]
  PIN i[53]
    DIRECTION INPUT ;
    USE SIGNAL ;
    PORT
      LAYER M5 ;
        RECT  5.808 0 5.832 0.084 ;
    END
  END i[53]
  PIN i[54]
    DIRECTION INPUT ;
    USE SIGNAL ;
    PORT
      LAYER M5 ;
        RECT  5.904 0 5.928 0.084 ;
    END
  END i[54]
  PIN i[55]
    DIRECTION INPUT ;
    USE SIGNAL ;
    PORT
      LAYER M5 ;
        RECT  6 0 6.024 0.084 ;
    END
  END i[55]
  PIN i[56]
    DIRECTION INPUT ;
    USE SIGNAL ;
    PORT
      LAYER M5 ;
        RECT  6.096 0 6.12 0.084 ;
    END
  END i[56]
  PIN i[57]
    DIRECTION INPUT ;
    USE SIGNAL ;
    PORT
      LAYER M5 ;
        RECT  6.192 0 6.216 0.084 ;
    END
  END i[57]
  PIN i[58]
    DIRECTION INPUT ;
    USE SIGNAL ;
    PORT
      LAYER M5 ;
        RECT  6.288 0 6.312 0.084 ;
    END
  END i[58]
  PIN i[59]
    DIRECTION INPUT ;
    USE SIGNAL ;
    PORT
      LAYER M5 ;
        RECT  6.384 0 6.408 0.084 ;
    END
  END i[59]
  PIN i[5]
    DIRECTION INPUT ;
    USE SIGNAL ;
    PORT
      LAYER M5 ;
        RECT  10.416 0 10.44 0.084 ;
    END
  END i[5]
  PIN i[60]
    DIRECTION INPUT ;
    USE SIGNAL ;
    PORT
      LAYER M5 ;
        RECT  6.48 0 6.504 0.084 ;
    END
  END i[60]
  PIN i[61]
    DIRECTION INPUT ;
    USE SIGNAL ;
    PORT
      LAYER M5 ;
        RECT  6.576 0 6.6 0.084 ;
    END
  END i[61]
  PIN i[62]
    DIRECTION INPUT ;
    USE SIGNAL ;
    PORT
      LAYER M5 ;
        RECT  6.672 0 6.696 0.084 ;
    END
  END i[62]
  PIN i[63]
    DIRECTION INPUT ;
    USE SIGNAL ;
    PORT
      LAYER M5 ;
        RECT  6.768 0 6.792 0.084 ;
    END
  END i[63]
  PIN i[64]
    DIRECTION INPUT ;
    USE SIGNAL ;
    PORT
      LAYER M5 ;
        RECT  0.72 0 0.744 0.084 ;
    END
  END i[64]
  PIN i[65]
    DIRECTION INPUT ;
    USE SIGNAL ;
    PORT
      LAYER M5 ;
        RECT  0.816 0 0.84 0.084 ;
    END
  END i[65]
  PIN i[66]
    DIRECTION INPUT ;
    USE SIGNAL ;
    PORT
      LAYER M5 ;
        RECT  0.912 0 0.936 0.084 ;
    END
  END i[66]
  PIN i[67]
    DIRECTION INPUT ;
    USE SIGNAL ;
    PORT
      LAYER M5 ;
        RECT  1.008 0 1.032 0.084 ;
    END
  END i[67]
  PIN i[68]
    DIRECTION INPUT ;
    USE SIGNAL ;
    PORT
      LAYER M5 ;
        RECT  1.104 0 1.128 0.084 ;
    END
  END i[68]
  PIN i[69]
    DIRECTION INPUT ;
    USE SIGNAL ;
    PORT
      LAYER M5 ;
        RECT  1.2 0 1.224 0.084 ;
    END
  END i[69]
  PIN i[6]
    DIRECTION INPUT ;
    USE SIGNAL ;
    PORT
      LAYER M5 ;
        RECT  10.512 0 10.536 0.084 ;
    END
  END i[6]
  PIN i[70]
    DIRECTION INPUT ;
    USE SIGNAL ;
    PORT
      LAYER M5 ;
        RECT  1.296 0 1.32 0.084 ;
    END
  END i[70]
  PIN i[71]
    DIRECTION INPUT ;
    USE SIGNAL ;
    PORT
      LAYER M5 ;
        RECT  1.392 0 1.416 0.084 ;
    END
  END i[71]
  PIN i[72]
    DIRECTION INPUT ;
    USE SIGNAL ;
    PORT
      LAYER M5 ;
        RECT  1.488 0 1.512 0.084 ;
    END
  END i[72]
  PIN i[73]
    DIRECTION INPUT ;
    USE SIGNAL ;
    PORT
      LAYER M5 ;
        RECT  1.584 0 1.608 0.084 ;
    END
  END i[73]
  PIN i[74]
    DIRECTION INPUT ;
    USE SIGNAL ;
    PORT
      LAYER M5 ;
        RECT  1.68 0 1.704 0.084 ;
    END
  END i[74]
  PIN i[75]
    DIRECTION INPUT ;
    USE SIGNAL ;
    PORT
      LAYER M5 ;
        RECT  1.776 0 1.8 0.084 ;
    END
  END i[75]
  PIN i[76]
    DIRECTION INPUT ;
    USE SIGNAL ;
    PORT
      LAYER M5 ;
        RECT  1.872 0 1.896 0.084 ;
    END
  END i[76]
  PIN i[77]
    DIRECTION INPUT ;
    USE SIGNAL ;
    PORT
      LAYER M5 ;
        RECT  1.968 0 1.992 0.084 ;
    END
  END i[77]
  PIN i[78]
    DIRECTION INPUT ;
    USE SIGNAL ;
    PORT
      LAYER M5 ;
        RECT  2.064 0 2.088 0.084 ;
    END
  END i[78]
  PIN i[79]
    DIRECTION INPUT ;
    USE SIGNAL ;
    PORT
      LAYER M5 ;
        RECT  2.16 0 2.184 0.084 ;
    END
  END i[79]
  PIN i[7]
    DIRECTION INPUT ;
    USE SIGNAL ;
    PORT
      LAYER M5 ;
        RECT  10.608 0 10.632 0.084 ;
    END
  END i[7]
  PIN i[80]
    DIRECTION INPUT ;
    USE SIGNAL ;
    PORT
      LAYER M5 ;
        RECT  2.256 0 2.28 0.084 ;
    END
  END i[80]
  PIN i[81]
    DIRECTION INPUT ;
    USE SIGNAL ;
    PORT
      LAYER M5 ;
        RECT  2.352 0 2.376 0.084 ;
    END
  END i[81]
  PIN i[82]
    DIRECTION INPUT ;
    USE SIGNAL ;
    PORT
      LAYER M5 ;
        RECT  2.448 0 2.472 0.084 ;
    END
  END i[82]
  PIN i[83]
    DIRECTION INPUT ;
    USE SIGNAL ;
    PORT
      LAYER M5 ;
        RECT  2.544 0 2.568 0.084 ;
    END
  END i[83]
  PIN i[84]
    DIRECTION INPUT ;
    USE SIGNAL ;
    PORT
      LAYER M5 ;
        RECT  2.64 0 2.664 0.084 ;
    END
  END i[84]
  PIN i[85]
    DIRECTION INPUT ;
    USE SIGNAL ;
    PORT
      LAYER M5 ;
        RECT  2.736 0 2.76 0.084 ;
    END
  END i[85]
  PIN i[86]
    DIRECTION INPUT ;
    USE SIGNAL ;
    PORT
      LAYER M5 ;
        RECT  2.832 0 2.856 0.084 ;
    END
  END i[86]
  PIN i[87]
    DIRECTION INPUT ;
    USE SIGNAL ;
    PORT
      LAYER M5 ;
        RECT  2.928 0 2.952 0.084 ;
    END
  END i[87]
  PIN i[88]
    DIRECTION INPUT ;
    USE SIGNAL ;
    PORT
      LAYER M5 ;
        RECT  3.024 0 3.048 0.084 ;
    END
  END i[88]
  PIN i[89]
    DIRECTION INPUT ;
    USE SIGNAL ;
    PORT
      LAYER M5 ;
        RECT  3.12 0 3.144 0.084 ;
    END
  END i[89]
  PIN i[8]
    DIRECTION INPUT ;
    USE SIGNAL ;
    PORT
      LAYER M5 ;
        RECT  10.704 0 10.728 0.084 ;
    END
  END i[8]
  PIN i[90]
    DIRECTION INPUT ;
    USE SIGNAL ;
    PORT
      LAYER M5 ;
        RECT  3.216 0 3.24 0.084 ;
    END
  END i[90]
  PIN i[91]
    DIRECTION INPUT ;
    USE SIGNAL ;
    PORT
      LAYER M5 ;
        RECT  3.312 0 3.336 0.084 ;
    END
  END i[91]
  PIN i[92]
    DIRECTION INPUT ;
    USE SIGNAL ;
    PORT
      LAYER M5 ;
        RECT  3.408 0 3.432 0.084 ;
    END
  END i[92]
  PIN i[93]
    DIRECTION INPUT ;
    USE SIGNAL ;
    PORT
      LAYER M5 ;
        RECT  3.504 0 3.528 0.084 ;
    END
  END i[93]
  PIN i[94]
    DIRECTION INPUT ;
    USE SIGNAL ;
    PORT
      LAYER M5 ;
        RECT  3.6 0 3.624 0.084 ;
    END
  END i[94]
  PIN i[95]
    DIRECTION INPUT ;
    USE SIGNAL ;
    PORT
      LAYER M5 ;
        RECT  3.696 0 3.72 0.084 ;
    END
  END i[95]
  PIN i[96]
    DIRECTION INPUT ;
    USE SIGNAL ;
    PORT
      LAYER M5 ;
        RECT  6.864 0 6.888 0.084 ;
    END
  END i[96]
  PIN i[97]
    DIRECTION INPUT ;
    USE SIGNAL ;
    PORT
      LAYER M5 ;
        RECT  6.96 0 6.984 0.084 ;
    END
  END i[97]
  PIN i[98]
    DIRECTION INPUT ;
    USE SIGNAL ;
    PORT
      LAYER M5 ;
        RECT  7.056 0 7.08 0.084 ;
    END
  END i[98]
  PIN i[99]
    DIRECTION INPUT ;
    USE SIGNAL ;
    PORT
      LAYER M5 ;
        RECT  7.152 0 7.176 0.084 ;
    END
  END i[99]
  PIN i[9]
    DIRECTION INPUT ;
    USE SIGNAL ;
    PORT
      LAYER M5 ;
        RECT  10.8 0 10.824 0.084 ;
    END
  END i[9]
  PIN o[0]
    DIRECTION OUTPUT ;
    USE SIGNAL ;
    PORT
      LAYER M5 ;
        RECT  24.624 23.676 24.648 23.76 ;
    END
  END o[0]
  PIN o[100]
    DIRECTION OUTPUT ;
    USE SIGNAL ;
    PORT
      LAYER M5 ;
        RECT  8.88 23.676 8.904 23.76 ;
    END
  END o[100]
  PIN o[101]
    DIRECTION OUTPUT ;
    USE SIGNAL ;
    PORT
      LAYER M5 ;
        RECT  8.976 23.676 9 23.76 ;
    END
  END o[101]
  PIN o[102]
    DIRECTION OUTPUT ;
    USE SIGNAL ;
    PORT
      LAYER M5 ;
        RECT  9.072 23.676 9.096 23.76 ;
    END
  END o[102]
  PIN o[103]
    DIRECTION OUTPUT ;
    USE SIGNAL ;
    PORT
      LAYER M5 ;
        RECT  9.168 23.676 9.192 23.76 ;
    END
  END o[103]
  PIN o[104]
    DIRECTION OUTPUT ;
    USE SIGNAL ;
    PORT
      LAYER M5 ;
        RECT  9.264 23.676 9.288 23.76 ;
    END
  END o[104]
  PIN o[105]
    DIRECTION OUTPUT ;
    USE SIGNAL ;
    PORT
      LAYER M5 ;
        RECT  9.36 23.676 9.384 23.76 ;
    END
  END o[105]
  PIN o[106]
    DIRECTION OUTPUT ;
    USE SIGNAL ;
    PORT
      LAYER M5 ;
        RECT  9.456 23.676 9.48 23.76 ;
    END
  END o[106]
  PIN o[107]
    DIRECTION OUTPUT ;
    USE SIGNAL ;
    PORT
      LAYER M5 ;
        RECT  9.552 23.676 9.576 23.76 ;
    END
  END o[107]
  PIN o[108]
    DIRECTION OUTPUT ;
    USE SIGNAL ;
    PORT
      LAYER M5 ;
        RECT  9.648 23.676 9.672 23.76 ;
    END
  END o[108]
  PIN o[109]
    DIRECTION OUTPUT ;
    USE SIGNAL ;
    PORT
      LAYER M5 ;
        RECT  9.744 23.676 9.768 23.76 ;
    END
  END o[109]
  PIN o[10]
    DIRECTION OUTPUT ;
    USE SIGNAL ;
    PORT
      LAYER M5 ;
        RECT  25.584 23.676 25.608 23.76 ;
    END
  END o[10]
  PIN o[110]
    DIRECTION OUTPUT ;
    USE SIGNAL ;
    PORT
      LAYER M5 ;
        RECT  9.84 23.676 9.864 23.76 ;
    END
  END o[110]
  PIN o[111]
    DIRECTION OUTPUT ;
    USE SIGNAL ;
    PORT
      LAYER M5 ;
        RECT  9.936 23.676 9.96 23.76 ;
    END
  END o[111]
  PIN o[112]
    DIRECTION OUTPUT ;
    USE SIGNAL ;
    PORT
      LAYER M5 ;
        RECT  10.032 23.676 10.056 23.76 ;
    END
  END o[112]
  PIN o[113]
    DIRECTION OUTPUT ;
    USE SIGNAL ;
    PORT
      LAYER M5 ;
        RECT  10.128 23.676 10.152 23.76 ;
    END
  END o[113]
  PIN o[114]
    DIRECTION OUTPUT ;
    USE SIGNAL ;
    PORT
      LAYER M5 ;
        RECT  10.224 23.676 10.248 23.76 ;
    END
  END o[114]
  PIN o[115]
    DIRECTION OUTPUT ;
    USE SIGNAL ;
    PORT
      LAYER M5 ;
        RECT  10.32 23.676 10.344 23.76 ;
    END
  END o[115]
  PIN o[116]
    DIRECTION OUTPUT ;
    USE SIGNAL ;
    PORT
      LAYER M5 ;
        RECT  10.416 23.676 10.44 23.76 ;
    END
  END o[116]
  PIN o[117]
    DIRECTION OUTPUT ;
    USE SIGNAL ;
    PORT
      LAYER M5 ;
        RECT  10.512 23.676 10.536 23.76 ;
    END
  END o[117]
  PIN o[118]
    DIRECTION OUTPUT ;
    USE SIGNAL ;
    PORT
      LAYER M5 ;
        RECT  10.608 23.676 10.632 23.76 ;
    END
  END o[118]
  PIN o[119]
    DIRECTION OUTPUT ;
    USE SIGNAL ;
    PORT
      LAYER M5 ;
        RECT  10.704 23.676 10.728 23.76 ;
    END
  END o[119]
  PIN o[11]
    DIRECTION OUTPUT ;
    USE SIGNAL ;
    PORT
      LAYER M5 ;
        RECT  25.68 23.676 25.704 23.76 ;
    END
  END o[11]
  PIN o[120]
    DIRECTION OUTPUT ;
    USE SIGNAL ;
    PORT
      LAYER M5 ;
        RECT  10.8 23.676 10.824 23.76 ;
    END
  END o[120]
  PIN o[121]
    DIRECTION OUTPUT ;
    USE SIGNAL ;
    PORT
      LAYER M5 ;
        RECT  10.896 23.676 10.92 23.76 ;
    END
  END o[121]
  PIN o[122]
    DIRECTION OUTPUT ;
    USE SIGNAL ;
    PORT
      LAYER M5 ;
        RECT  10.992 23.676 11.016 23.76 ;
    END
  END o[122]
  PIN o[123]
    DIRECTION OUTPUT ;
    USE SIGNAL ;
    PORT
      LAYER M5 ;
        RECT  11.088 23.676 11.112 23.76 ;
    END
  END o[123]
  PIN o[124]
    DIRECTION OUTPUT ;
    USE SIGNAL ;
    PORT
      LAYER M5 ;
        RECT  11.184 23.676 11.208 23.76 ;
    END
  END o[124]
  PIN o[125]
    DIRECTION OUTPUT ;
    USE SIGNAL ;
    PORT
      LAYER M5 ;
        RECT  11.28 23.676 11.304 23.76 ;
    END
  END o[125]
  PIN o[126]
    DIRECTION OUTPUT ;
    USE SIGNAL ;
    PORT
      LAYER M5 ;
        RECT  11.376 23.676 11.4 23.76 ;
    END
  END o[126]
  PIN o[127]
    DIRECTION OUTPUT ;
    USE SIGNAL ;
    PORT
      LAYER M5 ;
        RECT  11.472 23.676 11.496 23.76 ;
    END
  END o[127]
  PIN o[128]
    DIRECTION OUTPUT ;
    USE SIGNAL ;
    PORT
      LAYER M5 ;
        RECT  30.768 23.676 30.792 23.76 ;
    END
  END o[128]
  PIN o[129]
    DIRECTION OUTPUT ;
    USE SIGNAL ;
    PORT
      LAYER M5 ;
        RECT  30.864 23.676 30.888 23.76 ;
    END
  END o[129]
  PIN o[12]
    DIRECTION OUTPUT ;
    USE SIGNAL ;
    PORT
      LAYER M5 ;
        RECT  25.776 23.676 25.8 23.76 ;
    END
  END o[12]
  PIN o[130]
    DIRECTION OUTPUT ;
    USE SIGNAL ;
    PORT
      LAYER M5 ;
        RECT  30.96 23.676 30.984 23.76 ;
    END
  END o[130]
  PIN o[131]
    DIRECTION OUTPUT ;
    USE SIGNAL ;
    PORT
      LAYER M5 ;
        RECT  31.056 23.676 31.08 23.76 ;
    END
  END o[131]
  PIN o[132]
    DIRECTION OUTPUT ;
    USE SIGNAL ;
    PORT
      LAYER M5 ;
        RECT  31.152 23.676 31.176 23.76 ;
    END
  END o[132]
  PIN o[133]
    DIRECTION OUTPUT ;
    USE SIGNAL ;
    PORT
      LAYER M5 ;
        RECT  31.248 23.676 31.272 23.76 ;
    END
  END o[133]
  PIN o[134]
    DIRECTION OUTPUT ;
    USE SIGNAL ;
    PORT
      LAYER M5 ;
        RECT  31.344 23.676 31.368 23.76 ;
    END
  END o[134]
  PIN o[135]
    DIRECTION OUTPUT ;
    USE SIGNAL ;
    PORT
      LAYER M5 ;
        RECT  31.44 23.676 31.464 23.76 ;
    END
  END o[135]
  PIN o[136]
    DIRECTION OUTPUT ;
    USE SIGNAL ;
    PORT
      LAYER M5 ;
        RECT  31.536 23.676 31.56 23.76 ;
    END
  END o[136]
  PIN o[137]
    DIRECTION OUTPUT ;
    USE SIGNAL ;
    PORT
      LAYER M5 ;
        RECT  31.632 23.676 31.656 23.76 ;
    END
  END o[137]
  PIN o[138]
    DIRECTION OUTPUT ;
    USE SIGNAL ;
    PORT
      LAYER M5 ;
        RECT  31.728 23.676 31.752 23.76 ;
    END
  END o[138]
  PIN o[139]
    DIRECTION OUTPUT ;
    USE SIGNAL ;
    PORT
      LAYER M5 ;
        RECT  31.824 23.676 31.848 23.76 ;
    END
  END o[139]
  PIN o[13]
    DIRECTION OUTPUT ;
    USE SIGNAL ;
    PORT
      LAYER M5 ;
        RECT  25.872 23.676 25.896 23.76 ;
    END
  END o[13]
  PIN o[140]
    DIRECTION OUTPUT ;
    USE SIGNAL ;
    PORT
      LAYER M5 ;
        RECT  31.92 23.676 31.944 23.76 ;
    END
  END o[140]
  PIN o[141]
    DIRECTION OUTPUT ;
    USE SIGNAL ;
    PORT
      LAYER M5 ;
        RECT  32.016 23.676 32.04 23.76 ;
    END
  END o[141]
  PIN o[142]
    DIRECTION OUTPUT ;
    USE SIGNAL ;
    PORT
      LAYER M5 ;
        RECT  32.112 23.676 32.136 23.76 ;
    END
  END o[142]
  PIN o[143]
    DIRECTION OUTPUT ;
    USE SIGNAL ;
    PORT
      LAYER M5 ;
        RECT  32.208 23.676 32.232 23.76 ;
    END
  END o[143]
  PIN o[144]
    DIRECTION OUTPUT ;
    USE SIGNAL ;
    PORT
      LAYER M5 ;
        RECT  32.304 23.676 32.328 23.76 ;
    END
  END o[144]
  PIN o[145]
    DIRECTION OUTPUT ;
    USE SIGNAL ;
    PORT
      LAYER M5 ;
        RECT  32.4 23.676 32.424 23.76 ;
    END
  END o[145]
  PIN o[146]
    DIRECTION OUTPUT ;
    USE SIGNAL ;
    PORT
      LAYER M5 ;
        RECT  32.496 23.676 32.52 23.76 ;
    END
  END o[146]
  PIN o[147]
    DIRECTION OUTPUT ;
    USE SIGNAL ;
    PORT
      LAYER M5 ;
        RECT  32.592 23.676 32.616 23.76 ;
    END
  END o[147]
  PIN o[148]
    DIRECTION OUTPUT ;
    USE SIGNAL ;
    PORT
      LAYER M5 ;
        RECT  32.688 23.676 32.712 23.76 ;
    END
  END o[148]
  PIN o[149]
    DIRECTION OUTPUT ;
    USE SIGNAL ;
    PORT
      LAYER M5 ;
        RECT  32.784 23.676 32.808 23.76 ;
    END
  END o[149]
  PIN o[14]
    DIRECTION OUTPUT ;
    USE SIGNAL ;
    PORT
      LAYER M5 ;
        RECT  25.968 23.676 25.992 23.76 ;
    END
  END o[14]
  PIN o[150]
    DIRECTION OUTPUT ;
    USE SIGNAL ;
    PORT
      LAYER M5 ;
        RECT  32.88 23.676 32.904 23.76 ;
    END
  END o[150]
  PIN o[151]
    DIRECTION OUTPUT ;
    USE SIGNAL ;
    PORT
      LAYER M5 ;
        RECT  32.976 23.676 33 23.76 ;
    END
  END o[151]
  PIN o[152]
    DIRECTION OUTPUT ;
    USE SIGNAL ;
    PORT
      LAYER M5 ;
        RECT  33.072 23.676 33.096 23.76 ;
    END
  END o[152]
  PIN o[153]
    DIRECTION OUTPUT ;
    USE SIGNAL ;
    PORT
      LAYER M5 ;
        RECT  33.168 23.676 33.192 23.76 ;
    END
  END o[153]
  PIN o[154]
    DIRECTION OUTPUT ;
    USE SIGNAL ;
    PORT
      LAYER M5 ;
        RECT  33.264 23.676 33.288 23.76 ;
    END
  END o[154]
  PIN o[155]
    DIRECTION OUTPUT ;
    USE SIGNAL ;
    PORT
      LAYER M5 ;
        RECT  33.36 23.676 33.384 23.76 ;
    END
  END o[155]
  PIN o[156]
    DIRECTION OUTPUT ;
    USE SIGNAL ;
    PORT
      LAYER M5 ;
        RECT  33.456 23.676 33.48 23.76 ;
    END
  END o[156]
  PIN o[157]
    DIRECTION OUTPUT ;
    USE SIGNAL ;
    PORT
      LAYER M5 ;
        RECT  33.552 23.676 33.576 23.76 ;
    END
  END o[157]
  PIN o[158]
    DIRECTION OUTPUT ;
    USE SIGNAL ;
    PORT
      LAYER M5 ;
        RECT  33.648 23.676 33.672 23.76 ;
    END
  END o[158]
  PIN o[159]
    DIRECTION OUTPUT ;
    USE SIGNAL ;
    PORT
      LAYER M5 ;
        RECT  33.744 23.676 33.768 23.76 ;
    END
  END o[159]
  PIN o[15]
    DIRECTION OUTPUT ;
    USE SIGNAL ;
    PORT
      LAYER M5 ;
        RECT  26.064 23.676 26.088 23.76 ;
    END
  END o[15]
  PIN o[160]
    DIRECTION OUTPUT ;
    USE SIGNAL ;
    PORT
      LAYER M5 ;
        RECT  15.408 23.676 15.432 23.76 ;
    END
  END o[160]
  PIN o[161]
    DIRECTION OUTPUT ;
    USE SIGNAL ;
    PORT
      LAYER M5 ;
        RECT  15.504 23.676 15.528 23.76 ;
    END
  END o[161]
  PIN o[162]
    DIRECTION OUTPUT ;
    USE SIGNAL ;
    PORT
      LAYER M5 ;
        RECT  15.6 23.676 15.624 23.76 ;
    END
  END o[162]
  PIN o[163]
    DIRECTION OUTPUT ;
    USE SIGNAL ;
    PORT
      LAYER M5 ;
        RECT  15.696 23.676 15.72 23.76 ;
    END
  END o[163]
  PIN o[164]
    DIRECTION OUTPUT ;
    USE SIGNAL ;
    PORT
      LAYER M5 ;
        RECT  15.792 23.676 15.816 23.76 ;
    END
  END o[164]
  PIN o[165]
    DIRECTION OUTPUT ;
    USE SIGNAL ;
    PORT
      LAYER M5 ;
        RECT  15.888 23.676 15.912 23.76 ;
    END
  END o[165]
  PIN o[166]
    DIRECTION OUTPUT ;
    USE SIGNAL ;
    PORT
      LAYER M5 ;
        RECT  15.984 23.676 16.008 23.76 ;
    END
  END o[166]
  PIN o[167]
    DIRECTION OUTPUT ;
    USE SIGNAL ;
    PORT
      LAYER M5 ;
        RECT  16.08 23.676 16.104 23.76 ;
    END
  END o[167]
  PIN o[168]
    DIRECTION OUTPUT ;
    USE SIGNAL ;
    PORT
      LAYER M5 ;
        RECT  16.176 23.676 16.2 23.76 ;
    END
  END o[168]
  PIN o[169]
    DIRECTION OUTPUT ;
    USE SIGNAL ;
    PORT
      LAYER M5 ;
        RECT  16.272 23.676 16.296 23.76 ;
    END
  END o[169]
  PIN o[16]
    DIRECTION OUTPUT ;
    USE SIGNAL ;
    PORT
      LAYER M5 ;
        RECT  26.16 23.676 26.184 23.76 ;
    END
  END o[16]
  PIN o[170]
    DIRECTION OUTPUT ;
    USE SIGNAL ;
    PORT
      LAYER M5 ;
        RECT  16.368 23.676 16.392 23.76 ;
    END
  END o[170]
  PIN o[171]
    DIRECTION OUTPUT ;
    USE SIGNAL ;
    PORT
      LAYER M5 ;
        RECT  16.464 23.676 16.488 23.76 ;
    END
  END o[171]
  PIN o[172]
    DIRECTION OUTPUT ;
    USE SIGNAL ;
    PORT
      LAYER M5 ;
        RECT  16.56 23.676 16.584 23.76 ;
    END
  END o[172]
  PIN o[173]
    DIRECTION OUTPUT ;
    USE SIGNAL ;
    PORT
      LAYER M5 ;
        RECT  16.656 23.676 16.68 23.76 ;
    END
  END o[173]
  PIN o[174]
    DIRECTION OUTPUT ;
    USE SIGNAL ;
    PORT
      LAYER M5 ;
        RECT  16.752 23.676 16.776 23.76 ;
    END
  END o[174]
  PIN o[175]
    DIRECTION OUTPUT ;
    USE SIGNAL ;
    PORT
      LAYER M5 ;
        RECT  16.848 23.676 16.872 23.76 ;
    END
  END o[175]
  PIN o[176]
    DIRECTION OUTPUT ;
    USE SIGNAL ;
    PORT
      LAYER M5 ;
        RECT  16.944 23.676 16.968 23.76 ;
    END
  END o[176]
  PIN o[177]
    DIRECTION OUTPUT ;
    USE SIGNAL ;
    PORT
      LAYER M5 ;
        RECT  17.04 23.676 17.064 23.76 ;
    END
  END o[177]
  PIN o[178]
    DIRECTION OUTPUT ;
    USE SIGNAL ;
    PORT
      LAYER M5 ;
        RECT  17.136 23.676 17.16 23.76 ;
    END
  END o[178]
  PIN o[179]
    DIRECTION OUTPUT ;
    USE SIGNAL ;
    PORT
      LAYER M5 ;
        RECT  17.232 23.676 17.256 23.76 ;
    END
  END o[179]
  PIN o[17]
    DIRECTION OUTPUT ;
    USE SIGNAL ;
    PORT
      LAYER M5 ;
        RECT  26.256 23.676 26.28 23.76 ;
    END
  END o[17]
  PIN o[180]
    DIRECTION OUTPUT ;
    USE SIGNAL ;
    PORT
      LAYER M5 ;
        RECT  17.328 23.676 17.352 23.76 ;
    END
  END o[180]
  PIN o[181]
    DIRECTION OUTPUT ;
    USE SIGNAL ;
    PORT
      LAYER M5 ;
        RECT  17.424 23.676 17.448 23.76 ;
    END
  END o[181]
  PIN o[182]
    DIRECTION OUTPUT ;
    USE SIGNAL ;
    PORT
      LAYER M5 ;
        RECT  17.52 23.676 17.544 23.76 ;
    END
  END o[182]
  PIN o[183]
    DIRECTION OUTPUT ;
    USE SIGNAL ;
    PORT
      LAYER M5 ;
        RECT  17.616 23.676 17.64 23.76 ;
    END
  END o[183]
  PIN o[184]
    DIRECTION OUTPUT ;
    USE SIGNAL ;
    PORT
      LAYER M5 ;
        RECT  17.712 23.676 17.736 23.76 ;
    END
  END o[184]
  PIN o[185]
    DIRECTION OUTPUT ;
    USE SIGNAL ;
    PORT
      LAYER M5 ;
        RECT  17.808 23.676 17.832 23.76 ;
    END
  END o[185]
  PIN o[186]
    DIRECTION OUTPUT ;
    USE SIGNAL ;
    PORT
      LAYER M5 ;
        RECT  17.904 23.676 17.928 23.76 ;
    END
  END o[186]
  PIN o[187]
    DIRECTION OUTPUT ;
    USE SIGNAL ;
    PORT
      LAYER M5 ;
        RECT  18 23.676 18.024 23.76 ;
    END
  END o[187]
  PIN o[188]
    DIRECTION OUTPUT ;
    USE SIGNAL ;
    PORT
      LAYER M5 ;
        RECT  18.096 23.676 18.12 23.76 ;
    END
  END o[188]
  PIN o[189]
    DIRECTION OUTPUT ;
    USE SIGNAL ;
    PORT
      LAYER M5 ;
        RECT  18.192 23.676 18.216 23.76 ;
    END
  END o[189]
  PIN o[18]
    DIRECTION OUTPUT ;
    USE SIGNAL ;
    PORT
      LAYER M5 ;
        RECT  26.352 23.676 26.376 23.76 ;
    END
  END o[18]
  PIN o[190]
    DIRECTION OUTPUT ;
    USE SIGNAL ;
    PORT
      LAYER M5 ;
        RECT  18.288 23.676 18.312 23.76 ;
    END
  END o[190]
  PIN o[191]
    DIRECTION OUTPUT ;
    USE SIGNAL ;
    PORT
      LAYER M5 ;
        RECT  18.384 23.676 18.408 23.76 ;
    END
  END o[191]
  PIN o[192]
    DIRECTION OUTPUT ;
    USE SIGNAL ;
    PORT
      LAYER M5 ;
        RECT  18.48 23.676 18.504 23.76 ;
    END
  END o[192]
  PIN o[193]
    DIRECTION OUTPUT ;
    USE SIGNAL ;
    PORT
      LAYER M5 ;
        RECT  18.576 23.676 18.6 23.76 ;
    END
  END o[193]
  PIN o[194]
    DIRECTION OUTPUT ;
    USE SIGNAL ;
    PORT
      LAYER M5 ;
        RECT  18.672 23.676 18.696 23.76 ;
    END
  END o[194]
  PIN o[195]
    DIRECTION OUTPUT ;
    USE SIGNAL ;
    PORT
      LAYER M5 ;
        RECT  18.768 23.676 18.792 23.76 ;
    END
  END o[195]
  PIN o[196]
    DIRECTION OUTPUT ;
    USE SIGNAL ;
    PORT
      LAYER M5 ;
        RECT  18.864 23.676 18.888 23.76 ;
    END
  END o[196]
  PIN o[197]
    DIRECTION OUTPUT ;
    USE SIGNAL ;
    PORT
      LAYER M5 ;
        RECT  18.96 23.676 18.984 23.76 ;
    END
  END o[197]
  PIN o[198]
    DIRECTION OUTPUT ;
    USE SIGNAL ;
    PORT
      LAYER M5 ;
        RECT  19.056 23.676 19.08 23.76 ;
    END
  END o[198]
  PIN o[199]
    DIRECTION OUTPUT ;
    USE SIGNAL ;
    PORT
      LAYER M5 ;
        RECT  19.152 23.676 19.176 23.76 ;
    END
  END o[199]
  PIN o[19]
    DIRECTION OUTPUT ;
    USE SIGNAL ;
    PORT
      LAYER M5 ;
        RECT  26.448 23.676 26.472 23.76 ;
    END
  END o[19]
  PIN o[1]
    DIRECTION OUTPUT ;
    USE SIGNAL ;
    PORT
      LAYER M5 ;
        RECT  24.72 23.676 24.744 23.76 ;
    END
  END o[1]
  PIN o[200]
    DIRECTION OUTPUT ;
    USE SIGNAL ;
    PORT
      LAYER M5 ;
        RECT  19.248 23.676 19.272 23.76 ;
    END
  END o[200]
  PIN o[201]
    DIRECTION OUTPUT ;
    USE SIGNAL ;
    PORT
      LAYER M5 ;
        RECT  19.344 23.676 19.368 23.76 ;
    END
  END o[201]
  PIN o[202]
    DIRECTION OUTPUT ;
    USE SIGNAL ;
    PORT
      LAYER M5 ;
        RECT  19.44 23.676 19.464 23.76 ;
    END
  END o[202]
  PIN o[203]
    DIRECTION OUTPUT ;
    USE SIGNAL ;
    PORT
      LAYER M5 ;
        RECT  19.536 23.676 19.56 23.76 ;
    END
  END o[203]
  PIN o[204]
    DIRECTION OUTPUT ;
    USE SIGNAL ;
    PORT
      LAYER M5 ;
        RECT  19.632 23.676 19.656 23.76 ;
    END
  END o[204]
  PIN o[205]
    DIRECTION OUTPUT ;
    USE SIGNAL ;
    PORT
      LAYER M5 ;
        RECT  19.728 23.676 19.752 23.76 ;
    END
  END o[205]
  PIN o[206]
    DIRECTION OUTPUT ;
    USE SIGNAL ;
    PORT
      LAYER M5 ;
        RECT  19.824 23.676 19.848 23.76 ;
    END
  END o[206]
  PIN o[207]
    DIRECTION OUTPUT ;
    USE SIGNAL ;
    PORT
      LAYER M5 ;
        RECT  19.92 23.676 19.944 23.76 ;
    END
  END o[207]
  PIN o[208]
    DIRECTION OUTPUT ;
    USE SIGNAL ;
    PORT
      LAYER M5 ;
        RECT  20.016 23.676 20.04 23.76 ;
    END
  END o[208]
  PIN o[209]
    DIRECTION OUTPUT ;
    USE SIGNAL ;
    PORT
      LAYER M5 ;
        RECT  20.112 23.676 20.136 23.76 ;
    END
  END o[209]
  PIN o[20]
    DIRECTION OUTPUT ;
    USE SIGNAL ;
    PORT
      LAYER M5 ;
        RECT  26.544 23.676 26.568 23.76 ;
    END
  END o[20]
  PIN o[210]
    DIRECTION OUTPUT ;
    USE SIGNAL ;
    PORT
      LAYER M5 ;
        RECT  20.208 23.676 20.232 23.76 ;
    END
  END o[210]
  PIN o[211]
    DIRECTION OUTPUT ;
    USE SIGNAL ;
    PORT
      LAYER M5 ;
        RECT  20.304 23.676 20.328 23.76 ;
    END
  END o[211]
  PIN o[212]
    DIRECTION OUTPUT ;
    USE SIGNAL ;
    PORT
      LAYER M5 ;
        RECT  20.4 23.676 20.424 23.76 ;
    END
  END o[212]
  PIN o[213]
    DIRECTION OUTPUT ;
    USE SIGNAL ;
    PORT
      LAYER M5 ;
        RECT  20.496 23.676 20.52 23.76 ;
    END
  END o[213]
  PIN o[214]
    DIRECTION OUTPUT ;
    USE SIGNAL ;
    PORT
      LAYER M5 ;
        RECT  20.592 23.676 20.616 23.76 ;
    END
  END o[214]
  PIN o[215]
    DIRECTION OUTPUT ;
    USE SIGNAL ;
    PORT
      LAYER M5 ;
        RECT  20.688 23.676 20.712 23.76 ;
    END
  END o[215]
  PIN o[216]
    DIRECTION OUTPUT ;
    USE SIGNAL ;
    PORT
      LAYER M5 ;
        RECT  20.784 23.676 20.808 23.76 ;
    END
  END o[216]
  PIN o[217]
    DIRECTION OUTPUT ;
    USE SIGNAL ;
    PORT
      LAYER M5 ;
        RECT  20.88 23.676 20.904 23.76 ;
    END
  END o[217]
  PIN o[218]
    DIRECTION OUTPUT ;
    USE SIGNAL ;
    PORT
      LAYER M5 ;
        RECT  20.976 23.676 21 23.76 ;
    END
  END o[218]
  PIN o[219]
    DIRECTION OUTPUT ;
    USE SIGNAL ;
    PORT
      LAYER M5 ;
        RECT  21.072 23.676 21.096 23.76 ;
    END
  END o[219]
  PIN o[21]
    DIRECTION OUTPUT ;
    USE SIGNAL ;
    PORT
      LAYER M5 ;
        RECT  26.64 23.676 26.664 23.76 ;
    END
  END o[21]
  PIN o[220]
    DIRECTION OUTPUT ;
    USE SIGNAL ;
    PORT
      LAYER M5 ;
        RECT  21.168 23.676 21.192 23.76 ;
    END
  END o[220]
  PIN o[221]
    DIRECTION OUTPUT ;
    USE SIGNAL ;
    PORT
      LAYER M5 ;
        RECT  21.264 23.676 21.288 23.76 ;
    END
  END o[221]
  PIN o[222]
    DIRECTION OUTPUT ;
    USE SIGNAL ;
    PORT
      LAYER M5 ;
        RECT  21.36 23.676 21.384 23.76 ;
    END
  END o[222]
  PIN o[223]
    DIRECTION OUTPUT ;
    USE SIGNAL ;
    PORT
      LAYER M5 ;
        RECT  21.456 23.676 21.48 23.76 ;
    END
  END o[223]
  PIN o[224]
    DIRECTION OUTPUT ;
    USE SIGNAL ;
    PORT
      LAYER M5 ;
        RECT  21.552 23.676 21.576 23.76 ;
    END
  END o[224]
  PIN o[225]
    DIRECTION OUTPUT ;
    USE SIGNAL ;
    PORT
      LAYER M5 ;
        RECT  21.648 23.676 21.672 23.76 ;
    END
  END o[225]
  PIN o[226]
    DIRECTION OUTPUT ;
    USE SIGNAL ;
    PORT
      LAYER M5 ;
        RECT  21.744 23.676 21.768 23.76 ;
    END
  END o[226]
  PIN o[227]
    DIRECTION OUTPUT ;
    USE SIGNAL ;
    PORT
      LAYER M5 ;
        RECT  21.84 23.676 21.864 23.76 ;
    END
  END o[227]
  PIN o[228]
    DIRECTION OUTPUT ;
    USE SIGNAL ;
    PORT
      LAYER M5 ;
        RECT  21.936 23.676 21.96 23.76 ;
    END
  END o[228]
  PIN o[229]
    DIRECTION OUTPUT ;
    USE SIGNAL ;
    PORT
      LAYER M5 ;
        RECT  22.032 23.676 22.056 23.76 ;
    END
  END o[229]
  PIN o[22]
    DIRECTION OUTPUT ;
    USE SIGNAL ;
    PORT
      LAYER M5 ;
        RECT  26.736 23.676 26.76 23.76 ;
    END
  END o[22]
  PIN o[230]
    DIRECTION OUTPUT ;
    USE SIGNAL ;
    PORT
      LAYER M5 ;
        RECT  22.128 23.676 22.152 23.76 ;
    END
  END o[230]
  PIN o[231]
    DIRECTION OUTPUT ;
    USE SIGNAL ;
    PORT
      LAYER M5 ;
        RECT  22.224 23.676 22.248 23.76 ;
    END
  END o[231]
  PIN o[232]
    DIRECTION OUTPUT ;
    USE SIGNAL ;
    PORT
      LAYER M5 ;
        RECT  22.32 23.676 22.344 23.76 ;
    END
  END o[232]
  PIN o[233]
    DIRECTION OUTPUT ;
    USE SIGNAL ;
    PORT
      LAYER M5 ;
        RECT  22.416 23.676 22.44 23.76 ;
    END
  END o[233]
  PIN o[234]
    DIRECTION OUTPUT ;
    USE SIGNAL ;
    PORT
      LAYER M5 ;
        RECT  22.512 23.676 22.536 23.76 ;
    END
  END o[234]
  PIN o[235]
    DIRECTION OUTPUT ;
    USE SIGNAL ;
    PORT
      LAYER M5 ;
        RECT  22.608 23.676 22.632 23.76 ;
    END
  END o[235]
  PIN o[236]
    DIRECTION OUTPUT ;
    USE SIGNAL ;
    PORT
      LAYER M5 ;
        RECT  22.704 23.676 22.728 23.76 ;
    END
  END o[236]
  PIN o[237]
    DIRECTION OUTPUT ;
    USE SIGNAL ;
    PORT
      LAYER M5 ;
        RECT  22.8 23.676 22.824 23.76 ;
    END
  END o[237]
  PIN o[238]
    DIRECTION OUTPUT ;
    USE SIGNAL ;
    PORT
      LAYER M5 ;
        RECT  22.896 23.676 22.92 23.76 ;
    END
  END o[238]
  PIN o[239]
    DIRECTION OUTPUT ;
    USE SIGNAL ;
    PORT
      LAYER M5 ;
        RECT  22.992 23.676 23.016 23.76 ;
    END
  END o[239]
  PIN o[23]
    DIRECTION OUTPUT ;
    USE SIGNAL ;
    PORT
      LAYER M5 ;
        RECT  26.832 23.676 26.856 23.76 ;
    END
  END o[23]
  PIN o[240]
    DIRECTION OUTPUT ;
    USE SIGNAL ;
    PORT
      LAYER M5 ;
        RECT  23.088 23.676 23.112 23.76 ;
    END
  END o[240]
  PIN o[241]
    DIRECTION OUTPUT ;
    USE SIGNAL ;
    PORT
      LAYER M5 ;
        RECT  23.184 23.676 23.208 23.76 ;
    END
  END o[241]
  PIN o[242]
    DIRECTION OUTPUT ;
    USE SIGNAL ;
    PORT
      LAYER M5 ;
        RECT  23.28 23.676 23.304 23.76 ;
    END
  END o[242]
  PIN o[243]
    DIRECTION OUTPUT ;
    USE SIGNAL ;
    PORT
      LAYER M5 ;
        RECT  23.376 23.676 23.4 23.76 ;
    END
  END o[243]
  PIN o[244]
    DIRECTION OUTPUT ;
    USE SIGNAL ;
    PORT
      LAYER M5 ;
        RECT  23.472 23.676 23.496 23.76 ;
    END
  END o[244]
  PIN o[245]
    DIRECTION OUTPUT ;
    USE SIGNAL ;
    PORT
      LAYER M5 ;
        RECT  23.568 23.676 23.592 23.76 ;
    END
  END o[245]
  PIN o[246]
    DIRECTION OUTPUT ;
    USE SIGNAL ;
    PORT
      LAYER M5 ;
        RECT  23.664 23.676 23.688 23.76 ;
    END
  END o[246]
  PIN o[247]
    DIRECTION OUTPUT ;
    USE SIGNAL ;
    PORT
      LAYER M5 ;
        RECT  23.76 23.676 23.784 23.76 ;
    END
  END o[247]
  PIN o[248]
    DIRECTION OUTPUT ;
    USE SIGNAL ;
    PORT
      LAYER M5 ;
        RECT  23.856 23.676 23.88 23.76 ;
    END
  END o[248]
  PIN o[249]
    DIRECTION OUTPUT ;
    USE SIGNAL ;
    PORT
      LAYER M5 ;
        RECT  23.952 23.676 23.976 23.76 ;
    END
  END o[249]
  PIN o[24]
    DIRECTION OUTPUT ;
    USE SIGNAL ;
    PORT
      LAYER M5 ;
        RECT  26.928 23.676 26.952 23.76 ;
    END
  END o[24]
  PIN o[250]
    DIRECTION OUTPUT ;
    USE SIGNAL ;
    PORT
      LAYER M5 ;
        RECT  24.048 23.676 24.072 23.76 ;
    END
  END o[250]
  PIN o[251]
    DIRECTION OUTPUT ;
    USE SIGNAL ;
    PORT
      LAYER M5 ;
        RECT  24.144 23.676 24.168 23.76 ;
    END
  END o[251]
  PIN o[252]
    DIRECTION OUTPUT ;
    USE SIGNAL ;
    PORT
      LAYER M5 ;
        RECT  24.24 23.676 24.264 23.76 ;
    END
  END o[252]
  PIN o[253]
    DIRECTION OUTPUT ;
    USE SIGNAL ;
    PORT
      LAYER M5 ;
        RECT  24.336 23.676 24.36 23.76 ;
    END
  END o[253]
  PIN o[254]
    DIRECTION OUTPUT ;
    USE SIGNAL ;
    PORT
      LAYER M5 ;
        RECT  24.432 23.676 24.456 23.76 ;
    END
  END o[254]
  PIN o[255]
    DIRECTION OUTPUT ;
    USE SIGNAL ;
    PORT
      LAYER M5 ;
        RECT  24.528 23.676 24.552 23.76 ;
    END
  END o[255]
  PIN o[256]
    DIRECTION OUTPUT ;
    USE SIGNAL ;
    PORT
      LAYER M5 ;
        RECT  27.696 23.676 27.72 23.76 ;
    END
  END o[256]
  PIN o[257]
    DIRECTION OUTPUT ;
    USE SIGNAL ;
    PORT
      LAYER M5 ;
        RECT  27.792 23.676 27.816 23.76 ;
    END
  END o[257]
  PIN o[258]
    DIRECTION OUTPUT ;
    USE SIGNAL ;
    PORT
      LAYER M5 ;
        RECT  27.888 23.676 27.912 23.76 ;
    END
  END o[258]
  PIN o[259]
    DIRECTION OUTPUT ;
    USE SIGNAL ;
    PORT
      LAYER M5 ;
        RECT  27.984 23.676 28.008 23.76 ;
    END
  END o[259]
  PIN o[25]
    DIRECTION OUTPUT ;
    USE SIGNAL ;
    PORT
      LAYER M5 ;
        RECT  27.024 23.676 27.048 23.76 ;
    END
  END o[25]
  PIN o[260]
    DIRECTION OUTPUT ;
    USE SIGNAL ;
    PORT
      LAYER M5 ;
        RECT  28.08 23.676 28.104 23.76 ;
    END
  END o[260]
  PIN o[261]
    DIRECTION OUTPUT ;
    USE SIGNAL ;
    PORT
      LAYER M5 ;
        RECT  28.176 23.676 28.2 23.76 ;
    END
  END o[261]
  PIN o[262]
    DIRECTION OUTPUT ;
    USE SIGNAL ;
    PORT
      LAYER M5 ;
        RECT  28.272 23.676 28.296 23.76 ;
    END
  END o[262]
  PIN o[263]
    DIRECTION OUTPUT ;
    USE SIGNAL ;
    PORT
      LAYER M5 ;
        RECT  28.368 23.676 28.392 23.76 ;
    END
  END o[263]
  PIN o[264]
    DIRECTION OUTPUT ;
    USE SIGNAL ;
    PORT
      LAYER M5 ;
        RECT  28.464 23.676 28.488 23.76 ;
    END
  END o[264]
  PIN o[265]
    DIRECTION OUTPUT ;
    USE SIGNAL ;
    PORT
      LAYER M5 ;
        RECT  28.56 23.676 28.584 23.76 ;
    END
  END o[265]
  PIN o[266]
    DIRECTION OUTPUT ;
    USE SIGNAL ;
    PORT
      LAYER M5 ;
        RECT  28.656 23.676 28.68 23.76 ;
    END
  END o[266]
  PIN o[267]
    DIRECTION OUTPUT ;
    USE SIGNAL ;
    PORT
      LAYER M5 ;
        RECT  28.752 23.676 28.776 23.76 ;
    END
  END o[267]
  PIN o[268]
    DIRECTION OUTPUT ;
    USE SIGNAL ;
    PORT
      LAYER M5 ;
        RECT  28.848 23.676 28.872 23.76 ;
    END
  END o[268]
  PIN o[269]
    DIRECTION OUTPUT ;
    USE SIGNAL ;
    PORT
      LAYER M5 ;
        RECT  28.944 23.676 28.968 23.76 ;
    END
  END o[269]
  PIN o[26]
    DIRECTION OUTPUT ;
    USE SIGNAL ;
    PORT
      LAYER M5 ;
        RECT  27.12 23.676 27.144 23.76 ;
    END
  END o[26]
  PIN o[270]
    DIRECTION OUTPUT ;
    USE SIGNAL ;
    PORT
      LAYER M5 ;
        RECT  29.04 23.676 29.064 23.76 ;
    END
  END o[270]
  PIN o[271]
    DIRECTION OUTPUT ;
    USE SIGNAL ;
    PORT
      LAYER M5 ;
        RECT  29.136 23.676 29.16 23.76 ;
    END
  END o[271]
  PIN o[272]
    DIRECTION OUTPUT ;
    USE SIGNAL ;
    PORT
      LAYER M5 ;
        RECT  29.232 23.676 29.256 23.76 ;
    END
  END o[272]
  PIN o[273]
    DIRECTION OUTPUT ;
    USE SIGNAL ;
    PORT
      LAYER M5 ;
        RECT  29.328 23.676 29.352 23.76 ;
    END
  END o[273]
  PIN o[274]
    DIRECTION OUTPUT ;
    USE SIGNAL ;
    PORT
      LAYER M5 ;
        RECT  29.424 23.676 29.448 23.76 ;
    END
  END o[274]
  PIN o[275]
    DIRECTION OUTPUT ;
    USE SIGNAL ;
    PORT
      LAYER M5 ;
        RECT  29.52 23.676 29.544 23.76 ;
    END
  END o[275]
  PIN o[276]
    DIRECTION OUTPUT ;
    USE SIGNAL ;
    PORT
      LAYER M5 ;
        RECT  29.616 23.676 29.64 23.76 ;
    END
  END o[276]
  PIN o[277]
    DIRECTION OUTPUT ;
    USE SIGNAL ;
    PORT
      LAYER M5 ;
        RECT  29.712 23.676 29.736 23.76 ;
    END
  END o[277]
  PIN o[278]
    DIRECTION OUTPUT ;
    USE SIGNAL ;
    PORT
      LAYER M5 ;
        RECT  29.808 23.676 29.832 23.76 ;
    END
  END o[278]
  PIN o[279]
    DIRECTION OUTPUT ;
    USE SIGNAL ;
    PORT
      LAYER M5 ;
        RECT  29.904 23.676 29.928 23.76 ;
    END
  END o[279]
  PIN o[27]
    DIRECTION OUTPUT ;
    USE SIGNAL ;
    PORT
      LAYER M5 ;
        RECT  27.216 23.676 27.24 23.76 ;
    END
  END o[27]
  PIN o[280]
    DIRECTION OUTPUT ;
    USE SIGNAL ;
    PORT
      LAYER M5 ;
        RECT  30 23.676 30.024 23.76 ;
    END
  END o[280]
  PIN o[281]
    DIRECTION OUTPUT ;
    USE SIGNAL ;
    PORT
      LAYER M5 ;
        RECT  30.096 23.676 30.12 23.76 ;
    END
  END o[281]
  PIN o[282]
    DIRECTION OUTPUT ;
    USE SIGNAL ;
    PORT
      LAYER M5 ;
        RECT  30.192 23.676 30.216 23.76 ;
    END
  END o[282]
  PIN o[283]
    DIRECTION OUTPUT ;
    USE SIGNAL ;
    PORT
      LAYER M5 ;
        RECT  30.288 23.676 30.312 23.76 ;
    END
  END o[283]
  PIN o[284]
    DIRECTION OUTPUT ;
    USE SIGNAL ;
    PORT
      LAYER M5 ;
        RECT  30.384 23.676 30.408 23.76 ;
    END
  END o[284]
  PIN o[285]
    DIRECTION OUTPUT ;
    USE SIGNAL ;
    PORT
      LAYER M5 ;
        RECT  30.48 23.676 30.504 23.76 ;
    END
  END o[285]
  PIN o[286]
    DIRECTION OUTPUT ;
    USE SIGNAL ;
    PORT
      LAYER M5 ;
        RECT  30.576 23.676 30.6 23.76 ;
    END
  END o[286]
  PIN o[287]
    DIRECTION OUTPUT ;
    USE SIGNAL ;
    PORT
      LAYER M5 ;
        RECT  30.672 23.676 30.696 23.76 ;
    END
  END o[287]
  PIN o[288]
    DIRECTION OUTPUT ;
    USE SIGNAL ;
    PORT
      LAYER M5 ;
        RECT  13.104 23.676 13.128 23.76 ;
    END
  END o[288]
  PIN o[289]
    DIRECTION OUTPUT ;
    USE SIGNAL ;
    PORT
      LAYER M5 ;
        RECT  13.2 23.676 13.224 23.76 ;
    END
  END o[289]
  PIN o[28]
    DIRECTION OUTPUT ;
    USE SIGNAL ;
    PORT
      LAYER M5 ;
        RECT  27.312 23.676 27.336 23.76 ;
    END
  END o[28]
  PIN o[290]
    DIRECTION OUTPUT ;
    USE SIGNAL ;
    PORT
      LAYER M5 ;
        RECT  13.296 23.676 13.32 23.76 ;
    END
  END o[290]
  PIN o[291]
    DIRECTION OUTPUT ;
    USE SIGNAL ;
    PORT
      LAYER M5 ;
        RECT  13.392 23.676 13.416 23.76 ;
    END
  END o[291]
  PIN o[292]
    DIRECTION OUTPUT ;
    USE SIGNAL ;
    PORT
      LAYER M5 ;
        RECT  13.488 23.676 13.512 23.76 ;
    END
  END o[292]
  PIN o[293]
    DIRECTION OUTPUT ;
    USE SIGNAL ;
    PORT
      LAYER M5 ;
        RECT  13.584 23.676 13.608 23.76 ;
    END
  END o[293]
  PIN o[294]
    DIRECTION OUTPUT ;
    USE SIGNAL ;
    PORT
      LAYER M5 ;
        RECT  13.68 23.676 13.704 23.76 ;
    END
  END o[294]
  PIN o[295]
    DIRECTION OUTPUT ;
    USE SIGNAL ;
    PORT
      LAYER M5 ;
        RECT  13.776 23.676 13.8 23.76 ;
    END
  END o[295]
  PIN o[296]
    DIRECTION OUTPUT ;
    USE SIGNAL ;
    PORT
      LAYER M5 ;
        RECT  13.872 23.676 13.896 23.76 ;
    END
  END o[296]
  PIN o[297]
    DIRECTION OUTPUT ;
    USE SIGNAL ;
    PORT
      LAYER M5 ;
        RECT  13.968 23.676 13.992 23.76 ;
    END
  END o[297]
  PIN o[298]
    DIRECTION OUTPUT ;
    USE SIGNAL ;
    PORT
      LAYER M5 ;
        RECT  14.064 23.676 14.088 23.76 ;
    END
  END o[298]
  PIN o[299]
    DIRECTION OUTPUT ;
    USE SIGNAL ;
    PORT
      LAYER M5 ;
        RECT  14.16 23.676 14.184 23.76 ;
    END
  END o[299]
  PIN o[29]
    DIRECTION OUTPUT ;
    USE SIGNAL ;
    PORT
      LAYER M5 ;
        RECT  27.408 23.676 27.432 23.76 ;
    END
  END o[29]
  PIN o[2]
    DIRECTION OUTPUT ;
    USE SIGNAL ;
    PORT
      LAYER M5 ;
        RECT  24.816 23.676 24.84 23.76 ;
    END
  END o[2]
  PIN o[300]
    DIRECTION OUTPUT ;
    USE SIGNAL ;
    PORT
      LAYER M5 ;
        RECT  14.256 23.676 14.28 23.76 ;
    END
  END o[300]
  PIN o[301]
    DIRECTION OUTPUT ;
    USE SIGNAL ;
    PORT
      LAYER M5 ;
        RECT  14.352 23.676 14.376 23.76 ;
    END
  END o[301]
  PIN o[302]
    DIRECTION OUTPUT ;
    USE SIGNAL ;
    PORT
      LAYER M5 ;
        RECT  14.448 23.676 14.472 23.76 ;
    END
  END o[302]
  PIN o[303]
    DIRECTION OUTPUT ;
    USE SIGNAL ;
    PORT
      LAYER M5 ;
        RECT  14.544 23.676 14.568 23.76 ;
    END
  END o[303]
  PIN o[30]
    DIRECTION OUTPUT ;
    USE SIGNAL ;
    PORT
      LAYER M5 ;
        RECT  27.504 23.676 27.528 23.76 ;
    END
  END o[30]
  PIN o[31]
    DIRECTION OUTPUT ;
    USE SIGNAL ;
    PORT
      LAYER M5 ;
        RECT  27.6 23.676 27.624 23.76 ;
    END
  END o[31]
  PIN o[32]
    DIRECTION OUTPUT ;
    USE SIGNAL ;
    PORT
      LAYER M5 ;
        RECT  2.352 23.676 2.376 23.76 ;
    END
  END o[32]
  PIN o[33]
    DIRECTION OUTPUT ;
    USE SIGNAL ;
    PORT
      LAYER M5 ;
        RECT  2.448 23.676 2.472 23.76 ;
    END
  END o[33]
  PIN o[34]
    DIRECTION OUTPUT ;
    USE SIGNAL ;
    PORT
      LAYER M5 ;
        RECT  2.544 23.676 2.568 23.76 ;
    END
  END o[34]
  PIN o[35]
    DIRECTION OUTPUT ;
    USE SIGNAL ;
    PORT
      LAYER M5 ;
        RECT  2.64 23.676 2.664 23.76 ;
    END
  END o[35]
  PIN o[36]
    DIRECTION OUTPUT ;
    USE SIGNAL ;
    PORT
      LAYER M5 ;
        RECT  2.736 23.676 2.76 23.76 ;
    END
  END o[36]
  PIN o[37]
    DIRECTION OUTPUT ;
    USE SIGNAL ;
    PORT
      LAYER M5 ;
        RECT  2.832 23.676 2.856 23.76 ;
    END
  END o[37]
  PIN o[38]
    DIRECTION OUTPUT ;
    USE SIGNAL ;
    PORT
      LAYER M5 ;
        RECT  2.928 23.676 2.952 23.76 ;
    END
  END o[38]
  PIN o[39]
    DIRECTION OUTPUT ;
    USE SIGNAL ;
    PORT
      LAYER M5 ;
        RECT  3.024 23.676 3.048 23.76 ;
    END
  END o[39]
  PIN o[3]
    DIRECTION OUTPUT ;
    USE SIGNAL ;
    PORT
      LAYER M5 ;
        RECT  24.912 23.676 24.936 23.76 ;
    END
  END o[3]
  PIN o[40]
    DIRECTION OUTPUT ;
    USE SIGNAL ;
    PORT
      LAYER M5 ;
        RECT  3.12 23.676 3.144 23.76 ;
    END
  END o[40]
  PIN o[41]
    DIRECTION OUTPUT ;
    USE SIGNAL ;
    PORT
      LAYER M5 ;
        RECT  3.216 23.676 3.24 23.76 ;
    END
  END o[41]
  PIN o[42]
    DIRECTION OUTPUT ;
    USE SIGNAL ;
    PORT
      LAYER M5 ;
        RECT  3.312 23.676 3.336 23.76 ;
    END
  END o[42]
  PIN o[43]
    DIRECTION OUTPUT ;
    USE SIGNAL ;
    PORT
      LAYER M5 ;
        RECT  3.408 23.676 3.432 23.76 ;
    END
  END o[43]
  PIN o[44]
    DIRECTION OUTPUT ;
    USE SIGNAL ;
    PORT
      LAYER M5 ;
        RECT  3.504 23.676 3.528 23.76 ;
    END
  END o[44]
  PIN o[45]
    DIRECTION OUTPUT ;
    USE SIGNAL ;
    PORT
      LAYER M5 ;
        RECT  3.6 23.676 3.624 23.76 ;
    END
  END o[45]
  PIN o[46]
    DIRECTION OUTPUT ;
    USE SIGNAL ;
    PORT
      LAYER M5 ;
        RECT  3.696 23.676 3.72 23.76 ;
    END
  END o[46]
  PIN o[47]
    DIRECTION OUTPUT ;
    USE SIGNAL ;
    PORT
      LAYER M5 ;
        RECT  3.792 23.676 3.816 23.76 ;
    END
  END o[47]
  PIN o[48]
    DIRECTION OUTPUT ;
    USE SIGNAL ;
    PORT
      LAYER M5 ;
        RECT  3.888 23.676 3.912 23.76 ;
    END
  END o[48]
  PIN o[49]
    DIRECTION OUTPUT ;
    USE SIGNAL ;
    PORT
      LAYER M5 ;
        RECT  3.984 23.676 4.008 23.76 ;
    END
  END o[49]
  PIN o[4]
    DIRECTION OUTPUT ;
    USE SIGNAL ;
    PORT
      LAYER M5 ;
        RECT  25.008 23.676 25.032 23.76 ;
    END
  END o[4]
  PIN o[50]
    DIRECTION OUTPUT ;
    USE SIGNAL ;
    PORT
      LAYER M5 ;
        RECT  4.08 23.676 4.104 23.76 ;
    END
  END o[50]
  PIN o[51]
    DIRECTION OUTPUT ;
    USE SIGNAL ;
    PORT
      LAYER M5 ;
        RECT  4.176 23.676 4.2 23.76 ;
    END
  END o[51]
  PIN o[52]
    DIRECTION OUTPUT ;
    USE SIGNAL ;
    PORT
      LAYER M5 ;
        RECT  4.272 23.676 4.296 23.76 ;
    END
  END o[52]
  PIN o[53]
    DIRECTION OUTPUT ;
    USE SIGNAL ;
    PORT
      LAYER M5 ;
        RECT  4.368 23.676 4.392 23.76 ;
    END
  END o[53]
  PIN o[54]
    DIRECTION OUTPUT ;
    USE SIGNAL ;
    PORT
      LAYER M5 ;
        RECT  4.464 23.676 4.488 23.76 ;
    END
  END o[54]
  PIN o[55]
    DIRECTION OUTPUT ;
    USE SIGNAL ;
    PORT
      LAYER M5 ;
        RECT  4.56 23.676 4.584 23.76 ;
    END
  END o[55]
  PIN o[56]
    DIRECTION OUTPUT ;
    USE SIGNAL ;
    PORT
      LAYER M5 ;
        RECT  4.656 23.676 4.68 23.76 ;
    END
  END o[56]
  PIN o[57]
    DIRECTION OUTPUT ;
    USE SIGNAL ;
    PORT
      LAYER M5 ;
        RECT  4.752 23.676 4.776 23.76 ;
    END
  END o[57]
  PIN o[58]
    DIRECTION OUTPUT ;
    USE SIGNAL ;
    PORT
      LAYER M5 ;
        RECT  4.848 23.676 4.872 23.76 ;
    END
  END o[58]
  PIN o[59]
    DIRECTION OUTPUT ;
    USE SIGNAL ;
    PORT
      LAYER M5 ;
        RECT  4.944 23.676 4.968 23.76 ;
    END
  END o[59]
  PIN o[5]
    DIRECTION OUTPUT ;
    USE SIGNAL ;
    PORT
      LAYER M5 ;
        RECT  25.104 23.676 25.128 23.76 ;
    END
  END o[5]
  PIN o[60]
    DIRECTION OUTPUT ;
    USE SIGNAL ;
    PORT
      LAYER M5 ;
        RECT  5.04 23.676 5.064 23.76 ;
    END
  END o[60]
  PIN o[61]
    DIRECTION OUTPUT ;
    USE SIGNAL ;
    PORT
      LAYER M5 ;
        RECT  5.136 23.676 5.16 23.76 ;
    END
  END o[61]
  PIN o[62]
    DIRECTION OUTPUT ;
    USE SIGNAL ;
    PORT
      LAYER M5 ;
        RECT  5.232 23.676 5.256 23.76 ;
    END
  END o[62]
  PIN o[63]
    DIRECTION OUTPUT ;
    USE SIGNAL ;
    PORT
      LAYER M5 ;
        RECT  5.328 23.676 5.352 23.76 ;
    END
  END o[63]
  PIN o[64]
    DIRECTION OUTPUT ;
    USE SIGNAL ;
    PORT
      LAYER M5 ;
        RECT  5.424 23.676 5.448 23.76 ;
    END
  END o[64]
  PIN o[65]
    DIRECTION OUTPUT ;
    USE SIGNAL ;
    PORT
      LAYER M5 ;
        RECT  5.52 23.676 5.544 23.76 ;
    END
  END o[65]
  PIN o[66]
    DIRECTION OUTPUT ;
    USE SIGNAL ;
    PORT
      LAYER M5 ;
        RECT  5.616 23.676 5.64 23.76 ;
    END
  END o[66]
  PIN o[67]
    DIRECTION OUTPUT ;
    USE SIGNAL ;
    PORT
      LAYER M5 ;
        RECT  5.712 23.676 5.736 23.76 ;
    END
  END o[67]
  PIN o[68]
    DIRECTION OUTPUT ;
    USE SIGNAL ;
    PORT
      LAYER M5 ;
        RECT  5.808 23.676 5.832 23.76 ;
    END
  END o[68]
  PIN o[69]
    DIRECTION OUTPUT ;
    USE SIGNAL ;
    PORT
      LAYER M5 ;
        RECT  5.904 23.676 5.928 23.76 ;
    END
  END o[69]
  PIN o[6]
    DIRECTION OUTPUT ;
    USE SIGNAL ;
    PORT
      LAYER M5 ;
        RECT  25.2 23.676 25.224 23.76 ;
    END
  END o[6]
  PIN o[70]
    DIRECTION OUTPUT ;
    USE SIGNAL ;
    PORT
      LAYER M5 ;
        RECT  6 23.676 6.024 23.76 ;
    END
  END o[70]
  PIN o[71]
    DIRECTION OUTPUT ;
    USE SIGNAL ;
    PORT
      LAYER M5 ;
        RECT  6.096 23.676 6.12 23.76 ;
    END
  END o[71]
  PIN o[72]
    DIRECTION OUTPUT ;
    USE SIGNAL ;
    PORT
      LAYER M5 ;
        RECT  6.192 23.676 6.216 23.76 ;
    END
  END o[72]
  PIN o[73]
    DIRECTION OUTPUT ;
    USE SIGNAL ;
    PORT
      LAYER M5 ;
        RECT  6.288 23.676 6.312 23.76 ;
    END
  END o[73]
  PIN o[74]
    DIRECTION OUTPUT ;
    USE SIGNAL ;
    PORT
      LAYER M5 ;
        RECT  6.384 23.676 6.408 23.76 ;
    END
  END o[74]
  PIN o[75]
    DIRECTION OUTPUT ;
    USE SIGNAL ;
    PORT
      LAYER M5 ;
        RECT  6.48 23.676 6.504 23.76 ;
    END
  END o[75]
  PIN o[76]
    DIRECTION OUTPUT ;
    USE SIGNAL ;
    PORT
      LAYER M5 ;
        RECT  6.576 23.676 6.6 23.76 ;
    END
  END o[76]
  PIN o[77]
    DIRECTION OUTPUT ;
    USE SIGNAL ;
    PORT
      LAYER M5 ;
        RECT  6.672 23.676 6.696 23.76 ;
    END
  END o[77]
  PIN o[78]
    DIRECTION OUTPUT ;
    USE SIGNAL ;
    PORT
      LAYER M5 ;
        RECT  6.768 23.676 6.792 23.76 ;
    END
  END o[78]
  PIN o[79]
    DIRECTION OUTPUT ;
    USE SIGNAL ;
    PORT
      LAYER M5 ;
        RECT  6.864 23.676 6.888 23.76 ;
    END
  END o[79]
  PIN o[7]
    DIRECTION OUTPUT ;
    USE SIGNAL ;
    PORT
      LAYER M5 ;
        RECT  25.296 23.676 25.32 23.76 ;
    END
  END o[7]
  PIN o[80]
    DIRECTION OUTPUT ;
    USE SIGNAL ;
    PORT
      LAYER M5 ;
        RECT  6.96 23.676 6.984 23.76 ;
    END
  END o[80]
  PIN o[81]
    DIRECTION OUTPUT ;
    USE SIGNAL ;
    PORT
      LAYER M5 ;
        RECT  7.056 23.676 7.08 23.76 ;
    END
  END o[81]
  PIN o[82]
    DIRECTION OUTPUT ;
    USE SIGNAL ;
    PORT
      LAYER M5 ;
        RECT  7.152 23.676 7.176 23.76 ;
    END
  END o[82]
  PIN o[83]
    DIRECTION OUTPUT ;
    USE SIGNAL ;
    PORT
      LAYER M5 ;
        RECT  7.248 23.676 7.272 23.76 ;
    END
  END o[83]
  PIN o[84]
    DIRECTION OUTPUT ;
    USE SIGNAL ;
    PORT
      LAYER M5 ;
        RECT  7.344 23.676 7.368 23.76 ;
    END
  END o[84]
  PIN o[85]
    DIRECTION OUTPUT ;
    USE SIGNAL ;
    PORT
      LAYER M5 ;
        RECT  7.44 23.676 7.464 23.76 ;
    END
  END o[85]
  PIN o[86]
    DIRECTION OUTPUT ;
    USE SIGNAL ;
    PORT
      LAYER M5 ;
        RECT  7.536 23.676 7.56 23.76 ;
    END
  END o[86]
  PIN o[87]
    DIRECTION OUTPUT ;
    USE SIGNAL ;
    PORT
      LAYER M5 ;
        RECT  7.632 23.676 7.656 23.76 ;
    END
  END o[87]
  PIN o[88]
    DIRECTION OUTPUT ;
    USE SIGNAL ;
    PORT
      LAYER M5 ;
        RECT  7.728 23.676 7.752 23.76 ;
    END
  END o[88]
  PIN o[89]
    DIRECTION OUTPUT ;
    USE SIGNAL ;
    PORT
      LAYER M5 ;
        RECT  7.824 23.676 7.848 23.76 ;
    END
  END o[89]
  PIN o[8]
    DIRECTION OUTPUT ;
    USE SIGNAL ;
    PORT
      LAYER M5 ;
        RECT  25.392 23.676 25.416 23.76 ;
    END
  END o[8]
  PIN o[90]
    DIRECTION OUTPUT ;
    USE SIGNAL ;
    PORT
      LAYER M5 ;
        RECT  7.92 23.676 7.944 23.76 ;
    END
  END o[90]
  PIN o[91]
    DIRECTION OUTPUT ;
    USE SIGNAL ;
    PORT
      LAYER M5 ;
        RECT  8.016 23.676 8.04 23.76 ;
    END
  END o[91]
  PIN o[92]
    DIRECTION OUTPUT ;
    USE SIGNAL ;
    PORT
      LAYER M5 ;
        RECT  8.112 23.676 8.136 23.76 ;
    END
  END o[92]
  PIN o[93]
    DIRECTION OUTPUT ;
    USE SIGNAL ;
    PORT
      LAYER M5 ;
        RECT  8.208 23.676 8.232 23.76 ;
    END
  END o[93]
  PIN o[94]
    DIRECTION OUTPUT ;
    USE SIGNAL ;
    PORT
      LAYER M5 ;
        RECT  8.304 23.676 8.328 23.76 ;
    END
  END o[94]
  PIN o[95]
    DIRECTION OUTPUT ;
    USE SIGNAL ;
    PORT
      LAYER M5 ;
        RECT  8.4 23.676 8.424 23.76 ;
    END
  END o[95]
  PIN o[96]
    DIRECTION OUTPUT ;
    USE SIGNAL ;
    PORT
      LAYER M5 ;
        RECT  8.496 23.676 8.52 23.76 ;
    END
  END o[96]
  PIN o[97]
    DIRECTION OUTPUT ;
    USE SIGNAL ;
    PORT
      LAYER M5 ;
        RECT  8.592 23.676 8.616 23.76 ;
    END
  END o[97]
  PIN o[98]
    DIRECTION OUTPUT ;
    USE SIGNAL ;
    PORT
      LAYER M5 ;
        RECT  8.688 23.676 8.712 23.76 ;
    END
  END o[98]
  PIN o[99]
    DIRECTION OUTPUT ;
    USE SIGNAL ;
    PORT
      LAYER M5 ;
        RECT  8.784 23.676 8.808 23.76 ;
    END
  END o[99]
  PIN o[9]
    DIRECTION OUTPUT ;
    USE SIGNAL ;
    PORT
      LAYER M5 ;
        RECT  25.488 23.676 25.512 23.76 ;
    END
  END o[9]
  PIN rs
    DIRECTION INPUT ;
    USE SIGNAL ;
    PORT
      LAYER M4 ;
        RECT  0 15.888 0.084 15.912 ;
    END
  END rs
  PIN VDD
    DIRECTION INOUT ;
    USE POWER ;
    PORT
      LAYER M5 ;
        RECT  32.292 2.151 32.412 21.609 ;
        RECT  29.592 2.151 29.712 21.609 ;
        RECT  26.892 2.151 27.012 21.609 ;
        RECT  24.192 2.151 24.312 21.609 ;
        RECT  21.492 2.151 21.612 21.609 ;
        RECT  18.792 2.151 18.912 21.609 ;
        RECT  16.092 2.151 16.212 21.609 ;
        RECT  13.392 2.151 13.512 21.609 ;
        RECT  10.692 2.151 10.812 21.609 ;
        RECT  7.992 2.151 8.112 21.609 ;
        RECT  5.292 2.151 5.412 21.609 ;
        RECT  2.592 2.151 2.712 21.609 ;
    END
  END VDD
  PIN VSS
    DIRECTION INOUT ;
    USE GROUND ;
    PORT
      LAYER M5 ;
        RECT  32.1 2.137 32.22 21.623 ;
        RECT  29.4 2.137 29.52 21.623 ;
        RECT  26.7 2.137 26.82 21.623 ;
        RECT  24 2.137 24.12 21.623 ;
        RECT  21.3 2.137 21.42 21.623 ;
        RECT  18.6 2.137 18.72 21.623 ;
        RECT  15.9 2.137 16.02 21.623 ;
        RECT  13.2 2.137 13.32 21.623 ;
        RECT  10.5 2.137 10.62 21.623 ;
        RECT  7.8 2.137 7.92 21.623 ;
        RECT  5.1 2.137 5.22 21.623 ;
        RECT  2.4 2.137 2.52 21.623 ;
    END
  END VSS
  # OT_OBS_CLOSED layer=M5 d_um=1.536 added=55
  OBS
    LAYER RVTN ;
     RECT  2.16 2.16 32.4 2.295 ;
     RECT  2.16 2.565 32.4 2.835 ;
     RECT  2.16 3.105 32.4 3.375 ;
     RECT  2.16 3.645 32.4 3.915 ;
     RECT  2.16 4.185 32.4 4.455 ;
     RECT  2.16 4.725 32.4 4.995 ;
     RECT  2.16 5.265 32.4 5.535 ;
     RECT  2.16 5.805 32.4 6.075 ;
     RECT  2.16 6.345 32.4 6.615 ;
     RECT  2.16 6.885 32.4 7.155 ;
     RECT  2.16 7.425 32.4 7.695 ;
     RECT  2.16 7.965 32.4 8.235 ;
     RECT  2.16 8.505 32.4 8.775 ;
     RECT  2.16 9.045 32.4 9.315 ;
     RECT  2.16 9.585 32.4 9.855 ;
     RECT  2.16 10.125 32.4 10.395 ;
     RECT  2.16 10.665 32.4 10.935 ;
     RECT  2.16 11.205 32.4 11.475 ;
     RECT  2.16 11.745 32.4 12.015 ;
     RECT  2.16 12.285 32.4 12.555 ;
     RECT  2.16 12.825 32.4 13.095 ;
     RECT  2.16 13.365 32.4 13.635 ;
     RECT  2.16 13.905 32.4 14.175 ;
     RECT  2.16 14.445 32.4 14.715 ;
     RECT  2.16 14.985 32.4 15.255 ;
     RECT  2.16 15.525 32.4 15.795 ;
     RECT  2.16 16.065 32.4 16.335 ;
     RECT  2.16 16.605 32.4 16.875 ;
     RECT  2.16 17.145 32.4 17.415 ;
     RECT  2.16 17.685 32.4 17.955 ;
     RECT  2.16 18.225 32.4 18.495 ;
     RECT  2.16 18.765 32.4 19.035 ;
     RECT  2.16 19.305 32.4 19.575 ;
     RECT  2.16 19.845 32.4 20.115 ;
     RECT  2.16 20.385 32.4 20.655 ;
     RECT  2.16 20.925 32.4 21.195 ;
     RECT  2.16 21.465 32.4 21.6 ;
    LAYER RVTP ;
     RECT  2.16 2.295 32.4 2.565 ;
     RECT  2.16 2.835 32.4 3.105 ;
     RECT  2.16 3.375 32.4 3.645 ;
     RECT  2.16 3.915 32.4 4.185 ;
     RECT  2.16 4.455 32.4 4.725 ;
     RECT  2.16 4.995 32.4 5.265 ;
     RECT  2.16 5.535 32.4 5.805 ;
     RECT  2.16 6.075 32.4 6.345 ;
     RECT  2.16 6.615 32.4 6.885 ;
     RECT  2.16 7.155 32.4 7.425 ;
     RECT  2.16 7.695 32.4 7.965 ;
     RECT  2.16 8.235 32.4 8.505 ;
     RECT  2.16 8.775 32.4 9.045 ;
     RECT  2.16 9.315 32.4 9.585 ;
     RECT  2.16 9.855 32.4 10.125 ;
     RECT  2.16 10.395 32.4 10.665 ;
     RECT  2.16 10.935 32.4 11.205 ;
     RECT  2.16 11.475 32.4 11.745 ;
     RECT  2.16 12.015 32.4 12.285 ;
     RECT  2.16 12.555 32.4 12.825 ;
     RECT  2.16 13.095 32.4 13.365 ;
     RECT  2.16 13.635 32.4 13.905 ;
     RECT  2.16 14.175 32.4 14.445 ;
     RECT  2.16 14.715 32.4 14.985 ;
     RECT  2.16 15.255 32.4 15.525 ;
     RECT  2.16 15.795 32.4 16.065 ;
     RECT  2.16 16.335 32.4 16.605 ;
     RECT  2.16 16.875 32.4 17.145 ;
     RECT  2.16 17.415 32.4 17.685 ;
     RECT  2.16 17.955 32.4 18.225 ;
     RECT  2.16 18.495 32.4 18.765 ;
     RECT  2.16 19.035 32.4 19.305 ;
     RECT  2.16 19.575 32.4 19.845 ;
     RECT  2.16 20.115 32.4 20.385 ;
     RECT  2.16 20.655 32.4 20.925 ;
     RECT  2.16 21.195 32.4 21.465 ;
    LAYER M1 ;
     RECT  2.16 2.151 32.4 21.609 ;
    LAYER M2 ;
     RECT  0.751 6.012 1.723 6.03 ;
     RECT  1.723 3.852 1.831 4.14 ;
     RECT  1.795 4.932 1.831 4.95 ;
     RECT  1.831 3.852 1.903 4.95 ;
     RECT  1.903 3.852 2.083 5.058 ;
     RECT  1.723 6.012 2.083 6.57 ;
     RECT  1.795 2.772 2.155 2.79 ;
     RECT  2.083 3.852 2.155 6.57 ;
     RECT  2.155 2.772 2.16 6.57 ;
     RECT  2.155 11.016 2.16 11.034 ;
     RECT  2.16 2.151 12.307 21.609 ;
     RECT  12.307 2.151 13.703 21.654 ;
     RECT  13.703 2.151 14.827 21.609 ;
     RECT  14.827 2.151 15.035 21.654 ;
     RECT  15.035 2.151 21.631 21.609 ;
     RECT  21.631 2.106 22.775 21.609 ;
     RECT  22.775 2.151 24.763 21.609 ;
     RECT  24.763 2.106 25.115 21.609 ;
     RECT  25.771 1.152 26.195 1.17 ;
     RECT  25.115 2.151 31.099 21.609 ;
     RECT  31.099 2.106 31.315 21.609 ;
     RECT  31.315 2.106 31.703 21.654 ;
     RECT  31.703 2.151 32.4 21.654 ;
     RECT  32.4 2.421 32.412 21.654 ;
     RECT  32.412 16.416 32.459 18.792 ;
     RECT  32.459 16.416 32.495 18.216 ;
     RECT  32.412 15.336 32.531 15.354 ;
     RECT  32.495 17.658 32.639 18.216 ;
     RECT  32.412 19.656 32.711 21.654 ;
     RECT  32.639 18.198 32.783 18.216 ;
     RECT  32.711 19.926 32.855 21.654 ;
     RECT  32.855 20.196 32.999 21.654 ;
     RECT  32.999 20.196 33.071 20.682 ;
     RECT  32.999 21.474 33.071 21.654 ;
     RECT  33.071 21.474 33.107 21.564 ;
     RECT  33.107 21.546 33.143 21.564 ;
     RECT  33.071 20.664 33.647 20.682 ;
    LAYER M3 ;
     RECT  20.016 0.091 20.034 0.139 ;
     RECT  2.376 0.091 2.394 0.221 ;
     RECT  5.58 0.091 5.598 0.269 ;
     RECT  11.484 0.091 11.502 0.523 ;
     RECT  16.56 0.523 16.974 0.571 ;
     RECT  19.008 0.091 19.026 0.571 ;
     RECT  29.376 0.523 29.394 0.571 ;
     RECT  4.068 0.571 4.086 1.099 ;
     RECT  4.896 0.523 5.274 1.099 ;
     RECT  16.308 0.571 16.974 1.099 ;
     RECT  25.848 0.571 25.866 1.099 ;
     RECT  4.068 1.099 5.274 1.147 ;
     RECT  13.644 0.091 13.662 1.147 ;
     RECT  18.288 0.571 19.026 1.147 ;
     RECT  22.284 0.571 22.842 1.147 ;
     RECT  25.092 0.091 25.11 1.147 ;
     RECT  25.848 1.099 26.118 1.147 ;
     RECT  29.088 0.571 29.898 1.147 ;
     RECT  9.324 0.091 9.342 1.675 ;
     RECT  2.304 0.571 2.322 1.723 ;
     RECT  4.068 1.147 5.85 1.723 ;
     RECT  8.136 0.571 8.154 1.723 ;
     RECT  8.964 1.675 9.342 1.723 ;
     RECT  11.412 0.523 11.502 1.723 ;
     RECT  12.384 0.523 12.402 1.723 ;
     RECT  13.644 1.147 13.842 1.723 ;
     RECT  14.832 1.099 14.85 1.723 ;
     RECT  16.092 1.099 16.974 1.723 ;
     RECT  17.712 1.147 19.026 1.723 ;
     RECT  20.016 0.139 20.214 1.723 ;
     RECT  21.744 1.147 22.842 1.723 ;
     RECT  25.092 1.147 26.19 1.723 ;
     RECT  27.396 1.675 27.414 1.723 ;
     RECT  28.548 1.147 29.898 1.723 ;
     RECT  19.908 1.723 26.658 1.771 ;
     RECT  27.396 1.723 30.726 1.771 ;
     RECT  19.908 1.771 30.726 2.101 ;
     RECT  19.908 2.101 31.698 2.143 ;
     RECT  1.8 1.723 19.17 2.191 ;
     RECT  19.908 2.143 32.205 2.191 ;
     RECT  1.8 2.191 32.205 2.413 ;
     RECT  1.8 2.413 32.397 2.875 ;
     RECT  0.756 5.707 0.774 6.035 ;
     RECT  1.728 2.875 32.397 6.575 ;
     RECT  2.16 6.575 32.397 11.039 ;
     RECT  2.232 11.039 32.397 11.399 ;
     RECT  2.34 11.399 32.397 12.245 ;
     RECT  2.415 12.245 32.397 13.441 ;
     RECT  2.376 13.441 32.397 15.331 ;
     RECT  0.324 15.787 0.342 15.917 ;
     RECT  2.376 15.331 32.526 17.617 ;
     RECT  2.304 17.617 32.526 17.653 ;
     RECT  2.304 17.653 32.634 18.193 ;
     RECT  2.304 18.193 32.778 19.921 ;
     RECT  2.304 19.921 32.85 20.191 ;
     RECT  2.304 20.191 33.066 20.659 ;
     RECT  2.304 20.659 33.642 21.155 ;
     RECT  2.34 21.155 33.642 21.263 ;
     RECT  2.34 21.263 11.502 21.299 ;
     RECT  12.276 21.263 33.642 21.497 ;
     RECT  12.312 21.497 33.642 21.581 ;
     RECT  26.64 21.581 33.642 21.617 ;
     RECT  12.312 21.581 25.794 21.659 ;
     RECT  2.376 21.299 11.502 21.677 ;
     RECT  15.588 21.659 25.794 21.677 ;
     RECT  2.376 21.677 3.978 21.773 ;
     RECT  26.64 21.617 28.854 21.773 ;
     RECT  2.556 21.773 3.978 22.205 ;
     RECT  15.588 21.677 19.278 22.205 ;
     RECT  20.124 21.677 25.794 22.205 ;
     RECT  29.772 21.617 33.642 22.205 ;
     RECT  15.768 22.205 19.278 22.253 ;
     RECT  20.124 22.205 23.598 22.253 ;
     RECT  24.444 22.205 25.794 22.253 ;
     RECT  16.056 22.253 19.278 22.733 ;
     RECT  29.772 22.205 32.994 22.733 ;
     RECT  2.556 22.205 3.942 22.781 ;
     RECT  5.004 21.677 11.07 22.781 ;
     RECT  12.6 21.659 14.31 22.781 ;
     RECT  16.056 22.733 17.982 22.781 ;
     RECT  18.756 22.733 19.278 22.781 ;
     RECT  20.124 22.253 20.79 22.781 ;
     RECT  21.744 22.253 23.598 22.781 ;
     RECT  25.776 22.253 25.794 22.781 ;
     RECT  27.036 21.773 28.854 22.781 ;
     RECT  32.256 22.733 32.994 22.781 ;
     RECT  9.972 22.781 10.746 22.829 ;
     RECT  12.6 22.781 13.662 22.829 ;
     RECT  23.364 22.781 23.382 22.829 ;
     RECT  29.772 22.733 31.23 22.829 ;
     RECT  32.616 22.781 32.994 22.829 ;
     RECT  12.6 22.829 12.618 22.877 ;
     RECT  32.616 22.829 32.85 22.925 ;
     RECT  29.772 22.829 31.086 23.501 ;
     RECT  3.708 22.781 3.942 23.549 ;
     RECT  29.772 23.501 29.934 23.549 ;
     RECT  30.708 23.501 31.086 23.549 ;
     RECT  3.816 23.549 3.942 23.597 ;
     RECT  20.124 22.781 20.502 23.597 ;
     RECT  27.036 22.781 27.81 23.597 ;
     RECT  3.816 23.597 3.834 23.645 ;
     RECT  5.292 22.781 7.146 23.645 ;
     RECT  8.424 22.781 8.442 23.645 ;
     RECT  9.972 22.829 9.99 23.645 ;
     RECT  10.728 22.829 10.746 23.645 ;
     RECT  16.056 22.781 17.478 23.645 ;
     RECT  18.756 22.781 19.062 23.645 ;
     RECT  20.124 23.597 20.358 23.645 ;
     RECT  22.068 22.781 22.086 23.645 ;
     RECT  24.444 22.253 24.786 23.645 ;
     RECT  27.18 23.597 27.81 23.645 ;
     RECT  28.656 22.781 28.674 23.645 ;
     RECT  29.772 23.549 29.79 23.645 ;
     RECT  31.068 23.549 31.086 23.645 ;
     RECT  32.616 22.925 32.634 23.645 ;
    LAYER M4 ;
     RECT  0.06 15.792 0.353 15.912 ;
     RECT  0.701 5.712 0.785 5.736 ;
     RECT  0.181 7.68 0.901 7.704 ;
     RECT  0.901 7.68 0.997 8.568 ;
     RECT  0.805 2.88 1.093 2.904 ;
     RECT  1.189 3.984 1.285 4.008 ;
     RECT  1.285 3.984 1.477 4.584 ;
     RECT  0.997 6.864 1.573 8.568 ;
     RECT  1.745 1.728 2.245 1.752 ;
     RECT  1.093 2.88 2.245 2.952 ;
     RECT  1.669 0.576 2.293 0.6 ;
     RECT  2.293 0.192 2.321 0.6 ;
     RECT  2.321 0.096 2.333 0.6 ;
     RECT  2.245 1.728 2.408 2.952 ;
     RECT  1.477 3.984 2.408 4.68 ;
     RECT  1.573 6.864 2.408 8.76 ;
     RECT  0.353 15.792 2.408 15.816 ;
     RECT  2.293 19.872 2.408 19.896 ;
     RECT  2.321 21.744 2.408 21.768 ;
     RECT  2.293 23.424 2.437 23.448 ;
     RECT  2.333 0.096 2.438 0.216 ;
     RECT  2.437 22.752 2.677 23.448 ;
     RECT  2.408 1.728 2.704 21.768 ;
     RECT  2.438 0.144 2.819 0.168 ;
     RECT  2.704 4.56 2.905 9.672 ;
     RECT  2.704 15.792 3.197 16.536 ;
     RECT  2.704 21.648 3.26 21.768 ;
     RECT  2.677 22.752 3.26 23.592 ;
     RECT  3.26 21.648 3.269 23.592 ;
     RECT  3.269 21.648 3.347 22.248 ;
     RECT  3.347 21.648 3.443 22.2 ;
     RECT  3.269 23.52 3.493 23.592 ;
     RECT  2.704 14.256 3.601 14.28 ;
     RECT  3.493 23.52 3.737 23.64 ;
     RECT  2.704 11.376 3.797 11.4 ;
     RECT  3.797 11.328 3.841 11.4 ;
     RECT  3.737 23.568 3.845 23.64 ;
     RECT  2.905 4.944 3.913 9.672 ;
     RECT  3.841 11.328 3.913 11.64 ;
     RECT  2.704 1.728 3.923 2.28 ;
     RECT  3.845 23.568 3.953 23.592 ;
     RECT  2.704 18.192 3.973 20.616 ;
     RECT  3.443 22.176 3.989 22.2 ;
     RECT  3.197 16.512 4.165 16.536 ;
     RECT  4.057 13.632 4.301 13.656 ;
     RECT  3.913 3.696 4.381 3.72 ;
     RECT  3.913 4.944 4.381 11.64 ;
     RECT  4.057 0.576 4.417 0.6 ;
     RECT  3.923 1.728 4.417 1.752 ;
     RECT  3.973 18.192 4.453 21.096 ;
     RECT  4.381 3.696 4.489 11.64 ;
     RECT  4.165 16.512 4.549 17.112 ;
     RECT  4.453 18.192 4.549 21.768 ;
     RECT  4.417 0.576 4.595 1.752 ;
     RECT  4.489 3.696 4.633 11.928 ;
     RECT  4.595 0.576 4.885 0.6 ;
     RECT  4.595 1.68 4.981 1.752 ;
     RECT  4.837 22.752 5.033 22.776 ;
     RECT  4.549 16.512 5.075 21.768 ;
     RECT  4.981 1.68 5.108 1.848 ;
     RECT  4.633 2.88 5.108 11.928 ;
     RECT  4.301 13.056 5.108 13.656 ;
     RECT  4.669 14.832 5.108 14.856 ;
     RECT  5.075 16.512 5.108 21.72 ;
     RECT  4.885 0.528 5.125 0.6 ;
     RECT  5.125 0.336 5.173 0.6 ;
     RECT  5.108 1.68 5.404 21.72 ;
     RECT  5.173 0.144 5.554 0.6 ;
     RECT  5.125 23.52 5.603 23.64 ;
     RECT  5.554 0.096 5.713 0.6 ;
     RECT  5.404 1.68 5.713 1.752 ;
     RECT  5.713 0.096 5.795 1.752 ;
     RECT  5.795 0.096 5.843 0.12 ;
     RECT  5.404 2.88 5.933 11.976 ;
     RECT  5.795 1.152 5.939 1.752 ;
     RECT  5.404 15.408 5.939 21.72 ;
     RECT  5.404 13.056 5.977 13.128 ;
     RECT  5.939 1.2 6.035 1.752 ;
     RECT  5.939 15.408 6.049 19.416 ;
     RECT  5.939 20.544 6.221 21.72 ;
     RECT  6.049 16.032 6.265 19.416 ;
     RECT  6.221 21.552 6.277 21.72 ;
     RECT  5.933 2.88 6.365 5.64 ;
     RECT  6.265 16.032 6.371 16.056 ;
     RECT  6.265 17.04 6.437 19.416 ;
     RECT  6.437 17.136 6.467 19.416 ;
     RECT  6.277 21.552 6.509 22.2 ;
     RECT  6.365 3.36 6.515 5.64 ;
     RECT  5.603 23.616 6.565 23.64 ;
     RECT  5.933 6.816 6.659 11.4 ;
     RECT  6.467 17.616 6.697 19.416 ;
     RECT  5.977 13.104 6.829 13.128 ;
     RECT  6.221 20.544 6.929 20.568 ;
     RECT  6.035 1.728 6.937 1.752 ;
     RECT  6.829 13.104 7.225 13.752 ;
     RECT  6.659 6.816 7.261 10.2 ;
     RECT  6.929 19.92 7.292 20.568 ;
     RECT  6.509 21.552 7.292 21.672 ;
     RECT  7.477 0.144 7.573 0.168 ;
     RECT  7.573 0.144 7.669 0.216 ;
     RECT  6.697 17.616 7.669 18.84 ;
     RECT  7.669 0.144 7.763 0.264 ;
     RECT  6.937 1.728 7.808 2.328 ;
     RECT  6.515 3.36 7.808 5.304 ;
     RECT  7.261 6.288 7.808 10.2 ;
     RECT  6.659 11.376 7.808 11.4 ;
     RECT  7.225 13.056 7.808 13.752 ;
     RECT  7.669 16.896 7.808 18.84 ;
     RECT  7.292 19.92 7.808 21.672 ;
     RECT  7.763 0.192 7.859 0.264 ;
     RECT  7.859 0.24 7.955 0.264 ;
     RECT  7.808 1.728 8.081 21.672 ;
     RECT  8.081 1.728 8.104 21.72 ;
     RECT  8.081 0.576 8.165 0.6 ;
     RECT  8.104 16.896 8.165 17.112 ;
     RECT  8.104 18.144 8.165 21.72 ;
     RECT  8.104 3.408 8.273 6.36 ;
     RECT  8.165 17.04 8.381 17.112 ;
     RECT  6.565 22.752 8.453 23.64 ;
     RECT  8.165 18.144 8.561 21.672 ;
     RECT  8.561 19.392 8.569 21.672 ;
     RECT  8.381 17.04 8.633 17.064 ;
     RECT  8.569 20.544 8.921 21.672 ;
     RECT  8.104 1.728 8.953 1.944 ;
     RECT  8.953 1.68 9.011 1.944 ;
     RECT  8.273 3.408 9.029 6.312 ;
     RECT  8.104 7.68 9.029 10.296 ;
     RECT  9.029 3.936 9.101 6.312 ;
     RECT  8.921 21.312 9.107 21.672 ;
     RECT  9.011 1.68 9.203 1.896 ;
     RECT  9.107 21.648 9.233 21.672 ;
     RECT  8.453 22.752 9.233 22.776 ;
     RECT  9.101 5.664 9.241 6.312 ;
     RECT  9.029 7.68 9.241 9.144 ;
     RECT  9.233 21.648 9.317 22.776 ;
     RECT  8.561 18.144 9.349 18.264 ;
     RECT  8.104 11.376 9.353 11.4 ;
     RECT  9.241 5.664 9.461 9.144 ;
     RECT  9.313 0.096 9.491 0.12 ;
     RECT  9.349 17.52 9.541 18.264 ;
     RECT  8.569 19.392 9.541 19.416 ;
     RECT  9.541 17.52 9.673 19.416 ;
     RECT  9.317 22.752 9.821 22.776 ;
     RECT  9.203 1.728 10.069 1.896 ;
     RECT  9.317 21.648 10.072 21.72 ;
     RECT  9.101 3.936 10.105 4.68 ;
     RECT  9.461 5.664 10.105 7.704 ;
     RECT  9.461 9.024 10.105 9.144 ;
     RECT  9.029 10.128 10.105 10.296 ;
     RECT  10.261 0.144 10.357 0.168 ;
     RECT  10.072 21.6 10.46 21.72 ;
     RECT  10.069 1.728 10.465 1.944 ;
     RECT  10.465 1.728 10.508 2.04 ;
     RECT  10.105 3.936 10.508 7.704 ;
     RECT  10.105 9.024 10.508 10.296 ;
     RECT  9.889 11.952 10.508 11.976 ;
     RECT  10.249 14.688 10.508 14.712 ;
     RECT  9.673 17.52 10.508 19.992 ;
     RECT  10.46 21.6 10.508 21.768 ;
     RECT  10.508 1.728 10.547 21.768 ;
     RECT  10.547 1.728 10.739 21.72 ;
     RECT  9.829 22.8 10.757 23.64 ;
     RECT  10.739 1.728 10.804 21.672 ;
     RECT  10.804 1.728 10.835 2.04 ;
     RECT  10.757 22.8 10.835 22.824 ;
     RECT  10.804 8.976 10.865 9.048 ;
     RECT  10.804 4.128 10.973 5.736 ;
     RECT  10.804 18 11.045 18.168 ;
     RECT  11.045 18 11.081 18.024 ;
     RECT  10.804 19.344 11.081 20.52 ;
     RECT  10.885 22.752 11.081 22.776 ;
     RECT  10.357 0.144 11.401 0.216 ;
     RECT  11.081 19.344 11.405 19.704 ;
     RECT  11.401 0.144 11.429 0.552 ;
     RECT  10.804 21.6 11.449 21.672 ;
     RECT  11.429 0.096 11.513 0.552 ;
     RECT  11.449 21.648 11.513 21.672 ;
     RECT  10.973 4.656 11.621 5.736 ;
     RECT  10.804 10.128 11.941 10.248 ;
     RECT  11.941 10.128 11.987 10.968 ;
     RECT  10.835 1.728 12.553 1.848 ;
     RECT  12.553 1.728 12.625 1.896 ;
     RECT  11.621 4.656 12.841 4.776 ;
     RECT  10.804 6.72 12.877 7.8 ;
     RECT  12.589 22.848 12.949 22.872 ;
     RECT  10.865 8.976 13.021 9 ;
     RECT  11.987 10.224 13.021 10.968 ;
     RECT  12.949 22.8 13.085 22.872 ;
     RECT  13.021 3.648 13.093 3.672 ;
     RECT  12.841 4.656 13.093 5.112 ;
     RECT  13.093 3.648 13.201 5.112 ;
     RECT  12.625 1.728 13.208 2.328 ;
     RECT  13.201 3.648 13.208 5.208 ;
     RECT  12.877 6.336 13.208 7.8 ;
     RECT  13.021 8.976 13.208 10.968 ;
     RECT  12.853 14.928 13.208 14.952 ;
     RECT  11.405 19.344 13.208 19.368 ;
     RECT  13.085 22.176 13.208 22.872 ;
     RECT  13.208 1.728 13.285 22.872 ;
     RECT  11.513 0.528 13.331 0.552 ;
     RECT  13.285 1.728 13.429 23.448 ;
     RECT  13.429 1.728 13.504 23.544 ;
     RECT  13.504 20.496 13.523 23.544 ;
     RECT  13.504 1.728 13.601 9.912 ;
     RECT  13.504 14.928 13.601 15.432 ;
     RECT  13.523 22.752 13.619 23.544 ;
     RECT  13.381 0.144 13.633 0.168 ;
     RECT  13.633 0.096 13.667 0.168 ;
     RECT  13.601 1.728 13.715 9.672 ;
     RECT  13.619 22.752 13.715 22.824 ;
     RECT  13.667 0.096 13.811 0.12 ;
     RECT  13.715 1.728 13.813 2.904 ;
     RECT  13.813 1.152 13.907 2.904 ;
     RECT  13.504 16.56 13.955 16.584 ;
     RECT  13.715 3.936 13.961 9.672 ;
     RECT  13.523 20.496 14.003 21.72 ;
     RECT  13.907 2.88 14.105 2.904 ;
     RECT  13.961 4.992 14.177 9.672 ;
     RECT  13.601 15.312 14.185 15.432 ;
     RECT  14.177 5.04 14.321 9.672 ;
     RECT  13.715 22.752 14.321 22.776 ;
     RECT  13.504 12.192 14.531 12.216 ;
     RECT  14.185 15.312 14.627 15.336 ;
     RECT  13.907 1.152 14.821 1.896 ;
     RECT  14.003 20.496 14.821 21.624 ;
     RECT  14.821 19.968 14.857 21.624 ;
     RECT  14.821 1.104 15.109 1.896 ;
     RECT  14.857 19.632 15.26 21.624 ;
     RECT  13.961 3.936 15.325 3.96 ;
     RECT  14.321 5.568 15.325 9.672 ;
     RECT  15.26 19.584 15.397 21.624 ;
     RECT  15.325 3.408 15.541 9.672 ;
     RECT  14.821 13.824 15.577 13.848 ;
     RECT  15.397 19.584 15.721 22.2 ;
     RECT  15.721 18.768 15.74 22.2 ;
     RECT  15.109 1.104 15.757 2.28 ;
     RECT  15.757 1.104 15.908 2.328 ;
     RECT  15.541 3.408 15.908 9.72 ;
     RECT  13.504 10.944 15.908 10.968 ;
     RECT  15.577 12.864 15.908 13.848 ;
     RECT  15.301 17.088 15.908 17.112 ;
     RECT  15.74 18.768 15.908 22.248 ;
     RECT  15.589 23.568 15.973 23.592 ;
     RECT  15.908 1.104 16.121 22.248 ;
     RECT  16.121 1.728 16.204 22.248 ;
     RECT  16.165 0.576 16.337 0.6 ;
     RECT  16.204 14.928 16.355 14.952 ;
     RECT  16.204 15.936 16.355 16.008 ;
     RECT  16.204 17.424 16.381 22.248 ;
     RECT  16.204 11.376 16.453 11.4 ;
     RECT  16.381 20.544 16.499 22.248 ;
     RECT  16.381 17.424 16.517 19.224 ;
     RECT  16.517 19.2 16.553 19.224 ;
     RECT  16.204 4.656 16.589 9.384 ;
     RECT  15.973 23.568 16.604 23.64 ;
     RECT  16.355 15.936 16.769 15.96 ;
     RECT  16.589 5.568 17.021 9.384 ;
     RECT  16.517 17.424 17.093 18.216 ;
     RECT  16.508 0.528 17.171 0.552 ;
     RECT  16.204 1.728 17.269 1.896 ;
     RECT  16.204 13.056 17.449 13.848 ;
     RECT  16.604 22.704 17.489 23.64 ;
     RECT  16.499 20.544 17.521 21.672 ;
     RECT  17.449 12.528 17.533 13.848 ;
     RECT  17.269 1.728 17.555 2.328 ;
     RECT  17.557 11.952 17.641 11.976 ;
     RECT  17.555 1.728 17.701 2.28 ;
     RECT  17.521 19.824 17.701 21.672 ;
     RECT  17.489 22.704 17.701 23.592 ;
     RECT  17.701 1.152 17.785 2.28 ;
     RECT  17.701 3.936 17.845 3.96 ;
     RECT  17.021 5.568 17.845 7.224 ;
     RECT  17.701 19.824 17.917 23.592 ;
     RECT  17.021 8.496 17.989 9.384 ;
     RECT  17.917 19.344 18.035 23.592 ;
     RECT  18.035 22.704 18.137 23.592 ;
     RECT  18.277 0.576 18.361 0.6 ;
     RECT  18.181 18.24 18.373 18.264 ;
     RECT  17.785 1.728 18.608 2.28 ;
     RECT  17.845 3.936 18.608 7.224 ;
     RECT  17.989 8.448 18.608 9.384 ;
     RECT  17.305 10.608 18.608 10.632 ;
     RECT  17.533 13.056 18.608 13.848 ;
     RECT  18.373 17.52 18.608 18.264 ;
     RECT  18.035 19.344 18.608 21.72 ;
     RECT  18.137 22.752 18.661 23.592 ;
     RECT  18.608 1.728 18.904 21.72 ;
     RECT  18.853 0.096 19.037 0.12 ;
     RECT  18.904 1.728 19.109 1.8 ;
     RECT  18.904 3.408 19.109 9.384 ;
     RECT  18.904 17.088 19.253 21.72 ;
     RECT  19.253 17.088 19.649 21.672 ;
     RECT  18.904 15.408 19.667 15.432 ;
     RECT  19.649 17.088 19.793 17.112 ;
     RECT  19.649 18.24 19.865 21.672 ;
     RECT  19.109 3.408 19.916 4.2 ;
     RECT  19.916 3.36 20.003 4.2 ;
     RECT  19.109 5.52 20.005 9.384 ;
     RECT  18.904 10.608 20.005 10.632 ;
     RECT  20.005 0.096 20.088 0.12 ;
     RECT  20.088 0.096 20.089 0.168 ;
     RECT  19.109 1.728 20.113 1.752 ;
     RECT  20.005 5.52 20.117 10.632 ;
     RECT  20.003 3.408 20.149 4.2 ;
     RECT  20.149 3.408 20.221 4.344 ;
     RECT  20.117 5.52 20.221 8.76 ;
     RECT  20.089 0.144 20.225 0.168 ;
     RECT  18.661 22.752 20.369 23.64 ;
     RECT  20.053 12.528 20.485 12.552 ;
     RECT  18.904 13.824 20.485 13.848 ;
     RECT  19.865 18.48 20.581 21.672 ;
     RECT  20.369 22.752 20.581 23.592 ;
     RECT  20.117 10.176 20.617 10.632 ;
     RECT  20.113 1.728 20.725 1.896 ;
     RECT  20.617 10.176 20.773 10.824 ;
     RECT  20.581 18.48 21.013 23.592 ;
     RECT  20.221 3.408 21.157 8.76 ;
     RECT  20.773 10.176 21.157 11.4 ;
     RECT  21.013 17.616 21.157 23.592 ;
     RECT  20.725 1.728 21.308 2.28 ;
     RECT  21.157 3.408 21.308 11.4 ;
     RECT  20.485 12.528 21.308 13.848 ;
     RECT  20.917 15.84 21.308 15.864 ;
     RECT  21.157 17.376 21.308 23.592 ;
     RECT  21.308 1.728 21.485 23.592 ;
     RECT  21.485 1.728 21.491 21.768 ;
     RECT  21.491 1.728 21.587 21.72 ;
     RECT  21.587 1.728 21.604 21.672 ;
     RECT  21.604 1.728 21.733 2.28 ;
     RECT  21.485 22.752 21.829 23.592 ;
     RECT  21.733 1.152 21.875 2.28 ;
     RECT  21.604 15.84 22.025 15.864 ;
     RECT  21.604 17.088 22.06 21.672 ;
     RECT  22.06 17.184 22.097 21.672 ;
     RECT  21.829 22.752 22.097 23.64 ;
     RECT  21.604 4.128 22.205 10.2 ;
     RECT  21.875 1.152 22.273 1.848 ;
     RECT  22.273 0.576 22.277 1.848 ;
     RECT  21.604 12.528 22.277 14.28 ;
     RECT  22.633 15.984 22.717 16.008 ;
     RECT  22.741 12.192 22.853 12.312 ;
     RECT  22.277 0.576 22.876 0.6 ;
     RECT  22.097 17.616 22.885 21.672 ;
     RECT  22.097 22.752 22.885 22.776 ;
     RECT  22.277 1.728 23.065 1.848 ;
     RECT  22.885 17.616 23.173 22.776 ;
     RECT  23.065 1.728 23.281 1.896 ;
     RECT  23.173 17.136 23.353 22.776 ;
     RECT  22.205 4.128 23.42 9.912 ;
     RECT  23.029 11.232 23.509 11.256 ;
     RECT  23.353 17.136 23.609 22.824 ;
     RECT  23.42 3.456 23.641 9.912 ;
     RECT  23.509 11.184 23.641 11.256 ;
     RECT  23.609 17.136 23.789 22.2 ;
     RECT  23.281 1.728 24.008 2.328 ;
     RECT  23.641 3.456 24.008 11.256 ;
     RECT  22.853 12.288 24.008 12.312 ;
     RECT  22.277 13.824 24.008 14.28 ;
     RECT  23.789 17.136 24.008 21.816 ;
     RECT  24.008 1.728 24.304 21.816 ;
     RECT  23.941 23.232 24.325 23.592 ;
     RECT  24.304 17.088 24.401 21.816 ;
     RECT  24.229 0.144 24.419 0.168 ;
     RECT  24.325 23.232 24.467 23.64 ;
     RECT  24.467 23.568 24.515 23.64 ;
     RECT  24.515 23.616 24.797 23.64 ;
     RECT  24.304 1.728 24.851 9.672 ;
     RECT  24.851 3.456 24.941 9.672 ;
     RECT  24.401 17.088 24.977 21.72 ;
     RECT  24.304 12.288 25.121 12.552 ;
     RECT  25.081 0.096 25.165 0.12 ;
     RECT  24.851 1.728 25.273 2.328 ;
     RECT  24.977 17.136 25.381 21.72 ;
     RECT  25.381 17.136 25.517 22.248 ;
     RECT  25.517 17.136 25.661 21.576 ;
     RECT  25.661 20.064 25.715 21.576 ;
     RECT  25.657 15.36 25.741 15.384 ;
     RECT  25.765 22.752 25.849 22.776 ;
     RECT  25.273 1.728 25.957 1.896 ;
     RECT  24.941 3.456 25.981 9.384 ;
     RECT  25.837 0.576 26.089 0.6 ;
     RECT  25.957 1.68 26.089 1.896 ;
     RECT  26.089 0.576 26.291 1.896 ;
     RECT  25.981 3.456 26.377 9.672 ;
     RECT  25.661 17.136 26.437 18.984 ;
     RECT  26.291 1.728 26.521 1.896 ;
     RECT  25.715 20.304 26.629 21.576 ;
     RECT  26.521 1.728 26.708 2.04 ;
     RECT  26.377 3.456 26.708 9.72 ;
     RECT  25.621 10.704 26.708 10.728 ;
     RECT  25.121 12.528 26.708 12.552 ;
     RECT  24.304 13.824 26.708 13.848 ;
     RECT  26.437 16.992 26.708 18.984 ;
     RECT  26.629 20.304 26.708 21.768 ;
     RECT  26.708 1.728 26.713 21.768 ;
     RECT  26.245 23.568 26.821 23.592 ;
     RECT  26.713 1.728 27.004 21.72 ;
     RECT  26.821 23.424 27.109 23.592 ;
     RECT  27.004 17.616 27.137 20.328 ;
     RECT  27.109 23.424 27.155 23.64 ;
     RECT  26.917 0.144 27.203 0.216 ;
     RECT  27.004 3.36 27.209 9.672 ;
     RECT  27.203 0.144 27.299 0.168 ;
     RECT  27.209 7.104 27.299 9.672 ;
     RECT  27.004 16.512 27.353 16.536 ;
     RECT  27.004 21.648 27.353 21.72 ;
     RECT  27.004 1.728 27.385 1.992 ;
     RECT  27.004 13.824 27.395 14.28 ;
     RECT  27.385 1.68 27.443 1.992 ;
     RECT  27.137 17.856 27.539 20.328 ;
     RECT  27.209 3.36 27.683 6.12 ;
     RECT  27.539 18.096 27.821 20.328 ;
     RECT  27.004 12.528 27.997 12.552 ;
     RECT  27.395 13.824 27.997 13.848 ;
     RECT  27.821 19.968 28.033 20.328 ;
     RECT  27.973 22.128 28.217 22.2 ;
     RECT  27.443 1.68 28.225 1.896 ;
     RECT  27.683 4.992 28.357 6.12 ;
     RECT  28.217 22.176 28.421 22.2 ;
     RECT  27.155 23.616 28.421 23.64 ;
     RECT  28.225 1.68 28.537 1.8 ;
     RECT  28.421 22.176 28.685 23.64 ;
     RECT  28.357 4.992 28.753 6.216 ;
     RECT  28.685 22.176 28.793 23.592 ;
     RECT  28.793 22.752 28.865 23.592 ;
     RECT  28.249 17.088 28.933 17.112 ;
     RECT  28.033 19.968 28.933 20.52 ;
     RECT  27.299 7.296 28.969 9.672 ;
     RECT  28.309 11.376 28.969 11.4 ;
     RECT  28.933 16.8 28.981 17.112 ;
     RECT  27.821 18.096 28.981 18.84 ;
     RECT  28.933 19.92 28.981 20.52 ;
     RECT  28.537 1.152 29.077 1.8 ;
     RECT  28.753 4.608 29.077 6.216 ;
     RECT  28.981 16.8 29.077 20.52 ;
     RECT  29.077 4.512 29.084 6.216 ;
     RECT  28.969 7.296 29.084 11.4 ;
     RECT  29.077 16.56 29.125 20.52 ;
     RECT  27.683 3.36 29.257 3.384 ;
     RECT  29.077 0.576 29.267 1.8 ;
     RECT  29.267 1.728 29.329 1.8 ;
     RECT  29.257 2.784 29.329 3.384 ;
     RECT  29.267 0.576 29.365 0.6 ;
     RECT  29.329 1.728 29.408 3.384 ;
     RECT  29.084 4.512 29.408 11.4 ;
     RECT  27.997 12.528 29.408 13.848 ;
     RECT  29.125 15.84 29.408 20.52 ;
     RECT  29.408 1.728 29.704 21.612 ;
     RECT  28.865 23.376 29.761 23.592 ;
     RECT  29.365 0.528 29.843 0.6 ;
     RECT  29.761 23.376 29.845 23.64 ;
     RECT  29.704 15.408 29.939 21.612 ;
     RECT  29.843 0.576 29.953 0.6 ;
     RECT  29.845 23.376 29.987 23.592 ;
     RECT  29.704 11.328 30.017 13.848 ;
     RECT  29.939 18.672 30.044 21.612 ;
     RECT  29.939 15.408 30.083 17.688 ;
     RECT  29.704 5.088 30.089 10.248 ;
     RECT  30.044 18.672 30.131 21.672 ;
     RECT  30.089 7.296 30.197 9.528 ;
     RECT  30.017 11.328 30.197 13.224 ;
     RECT  30.197 7.776 30.233 9.528 ;
     RECT  30.233 7.776 30.269 9.336 ;
     RECT  30.269 7.776 30.377 9.288 ;
     RECT  30.197 11.328 30.485 11.592 ;
     RECT  30.197 13.2 30.593 13.224 ;
     RECT  30.083 15.408 30.697 17.64 ;
     RECT  29.704 1.728 30.737 3.384 ;
     RECT  30.089 5.088 30.773 6.072 ;
     RECT  30.737 2.256 30.809 3.384 ;
     RECT  30.377 7.776 30.809 8.52 ;
     RECT  30.809 8.496 30.845 8.52 ;
     RECT  30.773 5.568 30.989 6.072 ;
     RECT  29.987 23.424 31.057 23.592 ;
     RECT  30.485 11.328 31.069 11.4 ;
     RECT  30.697 15.36 31.091 17.64 ;
     RECT  31.091 15.36 31.093 15.864 ;
     RECT  31.093 15.072 31.165 15.864 ;
     RECT  31.057 23.424 31.196 23.64 ;
     RECT  30.131 18.672 31.301 21.144 ;
     RECT  31.301 18.672 31.633 21.672 ;
     RECT  31.196 22.8 31.633 23.64 ;
     RECT  31.165 4.512 31.849 4.536 ;
     RECT  30.989 5.568 31.849 5.88 ;
     RECT  30.809 2.88 32.108 2.904 ;
     RECT  31.849 4.512 32.108 5.88 ;
     RECT  31.069 11.328 32.108 11.352 ;
     RECT  31.165 14.208 32.108 15.864 ;
     RECT  31.091 17.04 32.108 17.64 ;
     RECT  31.633 18.672 32.108 23.64 ;
     RECT  32.108 2.148 32.212 23.64 ;
     RECT  32.212 2.418 32.404 23.64 ;
     RECT  32.404 21.072 32.645 23.64 ;
     RECT  32.404 19.92 32.833 19.944 ;
     RECT  32.645 21.072 33.299 22.92 ;
     RECT  33.299 21.648 33.491 22.92 ;
     RECT  33.491 21.648 33.587 22.296 ;
     RECT  33.587 21.648 33.697 22.2 ;
     RECT  33.697 21.648 33.779 21.672 ;
    LAYER M5 ;
     RECT  0.72 0.016 30.6 1.763 ;
     RECT  0.72 1.763 19.08 1.811 ;
     RECT  20.304 1.763 30.504 1.811 ;
     RECT  0.72 1.811 18.912 1.859 ;
     RECT  20.4 1.811 30.504 1.859 ;
     RECT  12.72 1.859 18.912 1.907 ;
     RECT  20.496 1.859 21.864 1.907 ;
     RECT  23.088 1.859 30.504 1.907 ;
     RECT  32.1 2.137 32.22 2.151 ;
     RECT  0.72 1.859 11.592 2.291 ;
     RECT  17.52 1.907 18.912 2.291 ;
     RECT  20.784 1.907 21.864 2.291 ;
     RECT  23.28 1.907 30.504 2.291 ;
     RECT  12.816 1.907 16.212 2.339 ;
     RECT  17.52 2.291 17.544 2.339 ;
     RECT  18.6 2.291 18.912 3.397 ;
     RECT  19.968 3.349 19.992 3.397 ;
     RECT  13.2 2.339 16.212 4.117 ;
     RECT  23.28 2.291 29.712 4.117 ;
     RECT  18.6 3.397 19.992 4.163 ;
     RECT  4.176 2.291 11.592 4.595 ;
     RECT  22.656 4.117 29.712 4.979 ;
     RECT  13.104 4.117 16.212 5.077 ;
     RECT  0.72 2.291 2.856 5.125 ;
     RECT  24 4.979 29.712 5.219 ;
     RECT  0.72 5.125 3.144 5.365 ;
     RECT  4.176 4.595 8.904 5.365 ;
     RECT  21.072 2.291 21.612 5.461 ;
     RECT  22.656 4.979 22.68 5.461 ;
     RECT  0.72 5.365 8.904 5.747 ;
     RECT  10.5 4.595 11.592 5.747 ;
     RECT  12.864 5.077 16.212 5.795 ;
     RECT  21.072 5.461 22.68 5.797 ;
     RECT  0.912 5.747 8.616 6.131 ;
     RECT  24 5.219 28.392 6.227 ;
     RECT  24 6.227 27.672 6.323 ;
     RECT  15.312 5.795 16.212 6.805 ;
     RECT  29.4 5.219 29.712 6.853 ;
     RECT  0.912 6.131 8.112 6.899 ;
     RECT  10.5 5.747 11.448 6.949 ;
     RECT  10.368 6.949 11.448 7.187 ;
     RECT  15.312 6.805 17.16 7.235 ;
     RECT  29.136 6.853 29.712 7.475 ;
     RECT  25.344 6.323 27.672 7.523 ;
     RECT  0.912 6.899 3.576 7.669 ;
     RECT  4.704 6.899 8.112 7.957 ;
     RECT  21.024 5.797 22.68 8.243 ;
     RECT  4.608 7.957 8.112 8.483 ;
     RECT  0.192 7.669 3.576 8.579 ;
     RECT  21.12 8.243 22.68 8.579 ;
     RECT  1.584 8.579 3.576 8.771 ;
     RECT  15.312 7.235 16.344 8.869 ;
     RECT  21.168 8.579 22.68 9.155 ;
     RECT  25.344 7.523 25.368 9.395 ;
     RECT  10.5 7.187 11.448 9.637 ;
     RECT  26.4 7.523 27.672 9.637 ;
     RECT  29.4 7.475 29.712 9.637 ;
     RECT  15.264 8.869 16.344 9.683 ;
     RECT  10.128 9.637 11.448 10.117 ;
     RECT  12.864 5.795 14.136 10.117 ;
     RECT  10.128 10.117 14.136 10.163 ;
     RECT  18.6 4.163 19.656 10.165 ;
     RECT  26.016 9.637 29.712 10.213 ;
     RECT  26.016 10.213 30.072 10.693 ;
     RECT  11.952 10.163 14.136 10.979 ;
     RECT  22.656 9.155 22.68 11.173 ;
     RECT  24 6.323 24.312 11.173 ;
     RECT  4.704 8.483 8.112 11.219 ;
     RECT  2.4 8.771 3.576 11.317 ;
     RECT  32.1 2.151 32.412 11.317 ;
     RECT  4.992 11.219 8.112 11.365 ;
     RECT  10.128 10.163 10.812 11.365 ;
     RECT  15.312 9.683 16.344 11.365 ;
     RECT  18.6 10.165 20.04 11.365 ;
     RECT  21.168 9.155 21.612 11.365 ;
     RECT  25.632 10.693 30.072 11.365 ;
     RECT  31.344 11.317 32.412 11.365 ;
     RECT  4.992 11.365 10.812 11.603 ;
     RECT  12.864 10.979 14.136 12.181 ;
     RECT  15.312 11.365 16.44 12.181 ;
     RECT  17.568 11.941 17.592 12.517 ;
     RECT  22.656 11.173 24.312 12.517 ;
     RECT  25.632 11.365 32.412 12.517 ;
     RECT  2.4 11.317 3.864 13.045 ;
     RECT  5.1 11.603 10.812 13.045 ;
     RECT  17.472 12.517 17.592 13.045 ;
     RECT  18.6 11.365 21.612 13.045 ;
     RECT  17.472 13.045 21.612 14.245 ;
     RECT  22.656 12.517 32.412 14.245 ;
     RECT  17.472 14.245 32.412 14.291 ;
     RECT  12.864 12.181 16.44 14.963 ;
     RECT  13.2 14.963 16.44 15.443 ;
     RECT  17.472 14.291 27.012 15.443 ;
     RECT  0.192 8.579 0.216 15.827 ;
     RECT  14.496 15.443 16.44 15.925 ;
     RECT  17.472 15.443 18.912 15.925 ;
     RECT  20.016 15.443 27.012 16.501 ;
     RECT  13.2 15.443 13.512 16.549 ;
     RECT  14.496 15.925 18.912 16.549 ;
     RECT  13.2 16.549 18.912 17.077 ;
     RECT  20.016 16.501 27.24 17.077 ;
     RECT  13.2 17.077 27.24 17.845 ;
     RECT  28.32 14.291 32.412 17.845 ;
     RECT  2.4 13.045 10.812 19.333 ;
     RECT  2.4 19.333 11.208 19.861 ;
     RECT  13.2 17.845 32.412 19.909 ;
     RECT  13.2 19.909 32.808 20.003 ;
     RECT  13.2 20.003 14.616 21.061 ;
     RECT  15.744 20.003 32.808 21.061 ;
     RECT  2.304 19.861 11.208 21.589 ;
     RECT  2.304 21.589 11.4 21.637 ;
     RECT  13.2 21.061 33.288 21.637 ;
     RECT  13.2 21.637 33.768 22.165 ;
     RECT  2.304 21.637 11.496 23.459 ;
     RECT  2.352 23.459 11.496 23.696 ;
     RECT  13.104 22.165 33.768 23.696 ;
     RECT  19.08 1.763 20.304 1.811 ;
     RECT  18.912 1.811 20.4 1.859 ;
     RECT  11.592 1.859 12.72 1.907 ;
     RECT  18.912 1.859 20.496 1.907 ;
     RECT  21.864 1.859 23.088 1.907 ;
     RECT  11.592 1.907 12.816 2.339 ;
     RECT  16.212 1.907 17.52 2.339 ;
     RECT  18.912 1.907 20.784 2.291 ;
     RECT  21.864 1.907 23.28 2.291 ;
     RECT  2.856 2.291 4.176 5.125 ;
     RECT  17.544 2.291 18.6 2.339 ;
     RECT  18.912 2.291 21.072 3.349 ;
     RECT  18.912 3.349 19.968 3.397 ;
     RECT  19.992 3.349 21.072 4.163 ;
     RECT  11.592 4.117 13.104 5.077 ;
     RECT  21.612 4.117 22.656 5.461 ;
     RECT  19.656 4.163 21.072 5.797 ;
     RECT  22.68 4.979 24 11.173 ;
     RECT  11.592 5.077 12.864 5.747 ;
     RECT  3.144 5.125 4.176 5.365 ;
     RECT  28.392 5.219 29.4 6.227 ;
     RECT  11.448 5.747 12.864 10.117 ;
     RECT  14.136 5.795 15.312 8.869 ;
     RECT  19.656 5.797 21.024 8.243 ;
     RECT  27.672 6.227 29.4 6.853 ;
     RECT  24.312 6.323 25.344 9.395 ;
     RECT  17.16 6.805 18.6 7.235 ;
     RECT  27.672 6.853 29.136 7.475 ;
     RECT  3.576 6.899 4.704 7.957 ;
     RECT  25.368 7.523 26.4 9.395 ;
     RECT  3.576 7.957 4.608 8.483 ;
     RECT  19.656 8.243 21.12 8.579 ;
     RECT  3.576 8.483 4.704 11.219 ;
     RECT  0.216 8.579 1.584 8.771 ;
     RECT  19.656 8.579 21.168 10.165 ;
     RECT  14.136 8.869 15.264 9.683 ;
     RECT  21.612 9.155 22.656 14.245 ;
     RECT  24.312 9.395 26.4 9.637 ;
     RECT  24.312 9.637 26.016 10.693 ;
     RECT  14.136 9.683 15.312 12.181 ;
     RECT  10.812 10.163 11.952 10.979 ;
     RECT  20.04 10.165 21.168 11.365 ;
     RECT  24.312 10.693 25.632 12.517 ;
     RECT  3.576 11.219 4.992 11.317 ;
     RECT  3.864 11.317 4.992 11.603 ;
     RECT  30.072 11.317 31.344 11.365 ;
     RECT  3.864 11.603 5.1 13.045 ;
     RECT  16.44 11.941 17.568 12.517 ;
     RECT  17.592 11.941 18.6 13.045 ;
     RECT  16.44 12.517 17.472 15.925 ;
     RECT  27.012 14.291 28.32 16.501 ;
     RECT  13.512 15.443 14.496 16.549 ;
     RECT  18.912 15.443 20.016 17.077 ;
     RECT  27.24 16.501 28.32 17.845 ;
     RECT  14.616 20.003 15.744 21.061 ;
  END
END hbfd_rly_304_SN
END LIBRARY
